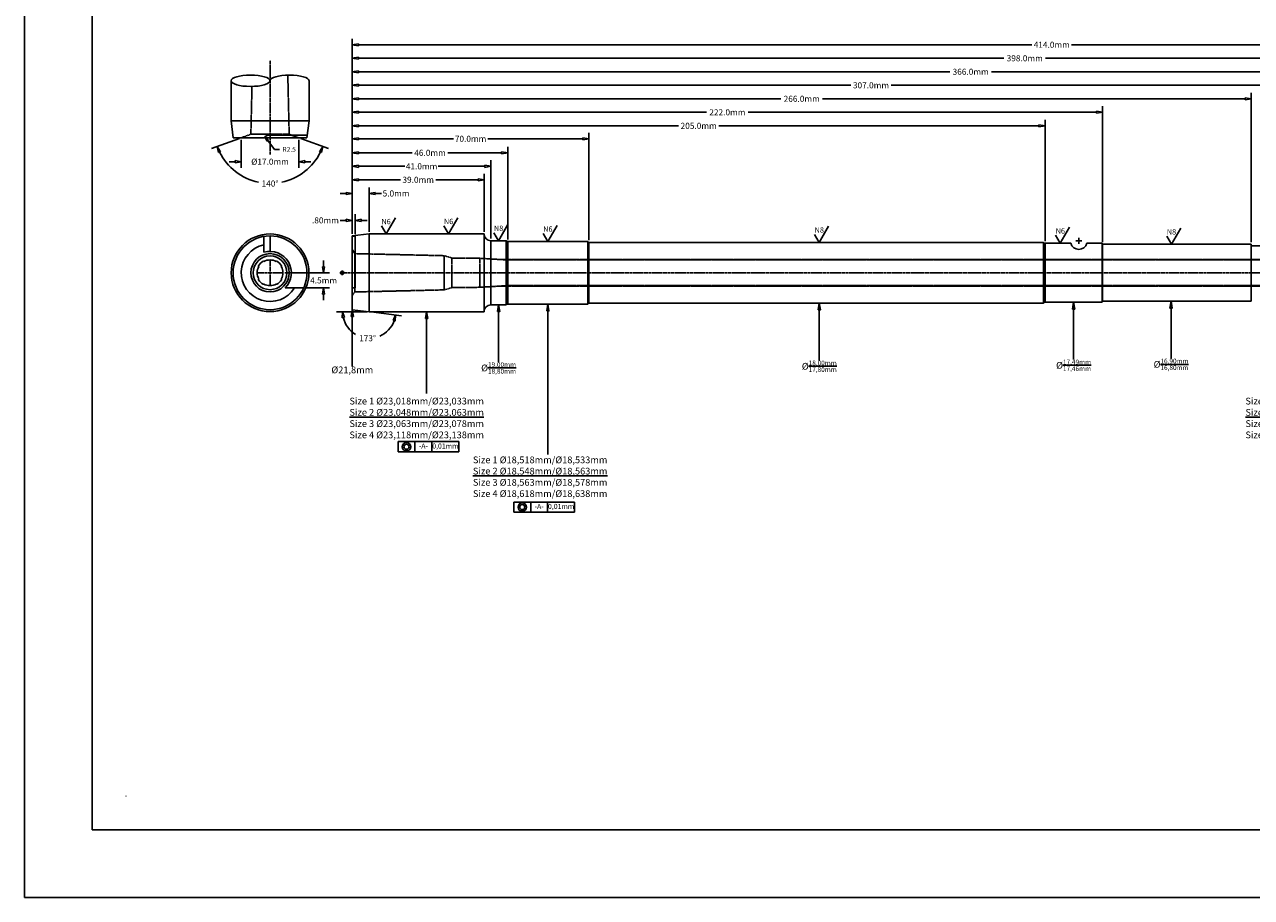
# Model space of a CAD drawing. Units: inches. Extents: x 0 to 594, y 0 to 420.
# Drawn here: x 0 to 363, y 0 to 259 of the extents above; entities that cross this region are included whole.
import ezdxf
from ezdxf.enums import TextEntityAlignment as Align

# ---------------------------------------------------------------- set-up
doc = ezdxf.new("R2010")
doc.units = ezdxf.units.IN
doc.header["$MEASUREMENT"] = 0
for name, pattern in [('CENTER2', [1.125, 0.75, -0.125, 0.125, -0.125]), ('HIDDEN2', [0.1875, 0.125, -0.0625]), ('PHANTOM', [2.5, 1.25, -0.25, 0.25, -0.25, 0.25, -0.25]), ('PHANTOM2', [1.25, 0.625, -0.125, 0.125, -0.125, 0.125, -0.125])]:
    doc.linetypes.add(name, pattern=pattern)
for name, color, linetype in [('BORDER', 7, 'Continuous'), ('BURNOUT', 7, 'Continuous'), ('CENTER', 1, 'CENTER2'), ('CENTERLINE', 1, 'CENTER2'), ('DIMENSION', 3, 'Continuous'), ('HATCH', 253, 'Continuous'), ('HIDDEN', 5, 'HIDDEN2'), ('OBJECT_HEAVY', 9, 'Continuous'), ('OBJECT_LIGHT', 7, 'Continuous'), ('PHANTOM', 252, 'PHANTOM'), ('SECTION', 6, 'PHANTOM2'), ('TEXT', 5, 'Continuous'), ('Title Block', 7, 'Continuous')]:
    doc.layers.add(name, color=color, linetype=linetype)
doc.dimstyles.get("Standard").update_dxf_attribs({"dimscale": 10, "dimtxt": 0.18, "dimasz": 0.18, "dimexe": 0.18, "dimexo": 0.0625, "dimgap": 0.09, "dimtad": 0, "dimtih": 1, "dimtoh": 1, "dimdec": 4, "dimzin": 0, "dimdsep": 46, "dimtxsty": 'Standard', "dimblk": 'CLOSEDBLANK', "dimcen": 0.09, "dimadec": 4, "dimazin": 0, "dimtfac": 1, "dimtdec": 4, "dimtofl": 0, "dimtmove": 0, "dimatfit": 3, "dimldrblk": 'CLOSEDBLANK', "dimfxl": 0, "dimtolj": 1, "dimtzin": 0, "dimarcsym": 0})
doc.dimstyles.new('Standard$0', dxfattribs={"dimscale": 10, "dimtxt": 0.18, "dimasz": 0.18, "dimexe": 0.18, "dimexo": 0.0625, "dimgap": 0.09, "dimtad": 0, "dimtih": 1, "dimtoh": 1, "dimdec": 4, "dimzin": 4, "dimdsep": 46, "dimtxsty": 'Standard', "dimblk": 'CLOSEDBLANK', "dimcen": 0.09, "dimadec": 5, "dimazin": 1, "dimtfac": 1, "dimtdec": 4, "dimtofl": 0, "dimtmove": 0, "dimatfit": 3, "dimldrblk": 'CLOSEDBLANK', "dimfxl": 0, "dimtolj": 1, "dimtzin": 0, "dimarcsym": 0})

# ---------------------------------------------------------------- blocks, each defined once
blk = doc.blocks.new('_ClosedBlank')
at = {"color": 0, "linetype": 'ByBlock', "lineweight": -2}
for p, q in [((-1, 0.17), (0, 0)), ((-1, 0.17), (-1, -0.17)), ((0, 0), (-1, -0.17))]:
    blk.add_line(p, q, dxfattribs=at)
blk = doc.blocks.new('*D21')
at = {"color": 0, "lineweight": -2}
for p, q in [((97, 196.55), (97, 254.33)), ((511, 192.52), (511, 254.33)), ((98.8, 252.53), (298.15, 252.53)), ((509.2, 252.53), (309.85, 252.53))]:
    blk.add_line(p, q, dxfattribs=at)
at = {"layer": 'Defpoints', "color": 0}
for p in [(511, 252.53), (97, 195.92), (511, 191.89)]:
    blk.add_point(p, dxfattribs=at)
at = {"color": 0, "lineweight": -2, "xscale": 1.8, "yscale": 1.8, "zscale": 1.8, "rotation": 180}
blk.add_blockref('_ClosedBlank', (97, 252.53), dxfattribs=at)
at = {"color": 0, "lineweight": -2, "xscale": 1.8, "yscale": 1.8, "zscale": 1.8}
blk.add_blockref('_ClosedBlank', (511, 252.53), dxfattribs=at)
at = {"color": 0, "insert": (304, 252.53), "char_height": 1.8, "attachment_point": 5}
blk.add_mtext('\\A1;414.0mm', dxfattribs=at)
blk = doc.blocks.new('*D7')
at = {"color": 0, "lineweight": -2}
for p, q in [((95.2, 200.53), (93.4, 200.53)), ((97, 196.55), (97, 202.33)), ((97.8, 196.43), (97.8, 202.33)), ((99.6, 200.53), (101.4, 200.53))]:
    blk.add_line(p, q, dxfattribs=at)
at = {"layer": 'Defpoints', "color": 0}
for p in [(97.8, 200.53), (97, 195.92), (97.8, 195.8)]:
    blk.add_point(p, dxfattribs=at)
at = {"color": 0, "lineweight": -2, "xscale": 1.8, "yscale": 1.8, "zscale": 1.8}
blk.add_blockref('_ClosedBlank', (97, 200.53), dxfattribs=at)
at = {"color": 0, "lineweight": -2, "xscale": 1.8, "yscale": 1.8, "zscale": 1.8, "rotation": 180}
blk.add_blockref('_ClosedBlank', (97.8, 200.53), dxfattribs=at)
at = {"color": 0, "insert": (89.05, 200.53), "char_height": 1.8, "attachment_point": 5}
blk.add_mtext('\\A1;.80mm', dxfattribs=at)
blk = doc.blocks.new('*D8')
at = {"color": 0, "lineweight": -2}
for p, q in [((95.2, 208.5), (93.4, 208.5)), ((97, 196.55), (97, 210.3)), ((102, 197.16), (102, 210.3)), ((103.8, 208.5), (105.6, 208.5))]:
    blk.add_line(p, q, dxfattribs=at)
at = {"layer": 'Defpoints', "color": 0}
for p in [(102, 208.5), (102, 196.54), (97, 195.92)]:
    blk.add_point(p, dxfattribs=at)
at = {"color": 0, "lineweight": -2, "xscale": 1.8, "yscale": 1.8, "zscale": 1.8}
blk.add_blockref('_ClosedBlank', (97, 208.5), dxfattribs=at)
at = {"color": 0, "lineweight": -2, "xscale": 1.8, "yscale": 1.8, "zscale": 1.8, "rotation": 180}
blk.add_blockref('_ClosedBlank', (102, 208.5), dxfattribs=at)
at = {"color": 0, "insert": (109.95, 208.5), "char_height": 1.8, "attachment_point": 5}
blk.add_mtext('\\A1;5.0mm', dxfattribs=at)
blk = doc.blocks.new('*D9')
at = {"color": 0, "lineweight": -2}
for p, q in [((97, 196.55), (97, 214.34)), ((136, 197.16), (136, 214.34)), ((98.8, 212.54), (111.25, 212.54)), ((134.2, 212.54), (121.75, 212.54))]:
    blk.add_line(p, q, dxfattribs=at)
at = {"layer": 'Defpoints', "color": 0}
for p in [(136, 212.54), (136, 196.54), (97, 195.92)]:
    blk.add_point(p, dxfattribs=at)
at = {"color": 0, "lineweight": -2, "xscale": 1.8, "yscale": 1.8, "zscale": 1.8, "rotation": 180}
blk.add_blockref('_ClosedBlank', (97, 212.54), dxfattribs=at)
at = {"color": 0, "lineweight": -2, "xscale": 1.8, "yscale": 1.8, "zscale": 1.8}
blk.add_blockref('_ClosedBlank', (136, 212.54), dxfattribs=at)
at = {"color": 0, "insert": (116.5, 212.54), "char_height": 1.8, "attachment_point": 5}
blk.add_mtext('\\A1;39.0mm', dxfattribs=at)
blk = doc.blocks.new('*D10')
at = {"color": 0, "lineweight": -2}
for p, q in [((97, 196.55), (97, 218.33)), ((138, 195.13), (138, 218.33)), ((98.8, 216.53), (112.55, 216.53)), ((136.2, 216.53), (122.45, 216.53))]:
    blk.add_line(p, q, dxfattribs=at)
at = {"layer": 'Defpoints', "color": 0}
for p in [(97, 216.53), (97, 195.92), (138, 194.5)]:
    blk.add_point(p, dxfattribs=at)
at = {"color": 0, "lineweight": -2, "xscale": 1.8, "yscale": 1.8, "zscale": 1.8, "rotation": 180}
blk.add_blockref('_ClosedBlank', (97, 216.53), dxfattribs=at)
at = {"color": 0, "lineweight": -2, "xscale": 1.8, "yscale": 1.8, "zscale": 1.8}
blk.add_blockref('_ClosedBlank', (138, 216.53), dxfattribs=at)
at = {"color": 0, "insert": (117.5, 216.53), "char_height": 1.8, "attachment_point": 5}
blk.add_mtext('\\A1;41.0mm', dxfattribs=at)
blk = doc.blocks.new('*D11')
at = {"color": 0, "lineweight": -2}
for p, q in [((97, 196.55), (97, 222.33)), ((143, 194.9), (143, 222.33)), ((98.8, 220.53), (114.75, 220.53)), ((141.2, 220.53), (125.25, 220.53))]:
    blk.add_line(p, q, dxfattribs=at)
at = {"layer": 'Defpoints', "color": 0}
for p in [(97, 220.53), (97, 195.92), (143, 194.28)]:
    blk.add_point(p, dxfattribs=at)
at = {"color": 0, "lineweight": -2, "xscale": 1.8, "yscale": 1.8, "zscale": 1.8, "rotation": 180}
blk.add_blockref('_ClosedBlank', (97, 220.53), dxfattribs=at)
at = {"color": 0, "lineweight": -2, "xscale": 1.8, "yscale": 1.8, "zscale": 1.8}
blk.add_blockref('_ClosedBlank', (143, 220.53), dxfattribs=at)
at = {"color": 0, "insert": (120, 220.53), "char_height": 1.8, "attachment_point": 5}
blk.add_mtext('\\A1;46.0mm', dxfattribs=at)
blk = doc.blocks.new('*D12')
at = {"color": 0, "lineweight": -2}
for p, q in [((97, 196.55), (97, 226.48)), ((167, 194.63), (167, 226.48)), ((98.8, 224.68), (126.9, 224.68)), ((165.2, 224.68), (137.1, 224.68))]:
    blk.add_line(p, q, dxfattribs=at)
at = {"layer": 'Defpoints', "color": 0}
for p in [(97, 224.68), (97, 195.92), (167, 194)]:
    blk.add_point(p, dxfattribs=at)
at = {"color": 0, "lineweight": -2, "xscale": 1.8, "yscale": 1.8, "zscale": 1.8, "rotation": 180}
blk.add_blockref('_ClosedBlank', (97, 224.68), dxfattribs=at)
at = {"color": 0, "lineweight": -2, "xscale": 1.8, "yscale": 1.8, "zscale": 1.8}
blk.add_blockref('_ClosedBlank', (167, 224.68), dxfattribs=at)
at = {"color": 0, "insert": (132, 224.68), "char_height": 1.8, "attachment_point": 5}
blk.add_mtext('\\A1;70.0mm', dxfattribs=at)
blk = doc.blocks.new('*D13')
at = {"color": 0, "lineweight": -2}
for p, q in [((97, 196.55), (97, 230.33)), ((302, 194.35), (302, 230.33)), ((98.8, 228.53), (193.5, 228.53)), ((300.2, 228.53), (205.5, 228.53))]:
    blk.add_line(p, q, dxfattribs=at)
at = {"layer": 'Defpoints', "color": 0}
for p in [(97, 228.53), (97, 195.92), (302, 193.73)]:
    blk.add_point(p, dxfattribs=at)
at = {"color": 0, "lineweight": -2, "xscale": 1.8, "yscale": 1.8, "zscale": 1.8, "rotation": 180}
blk.add_blockref('_ClosedBlank', (97, 228.53), dxfattribs=at)
at = {"color": 0, "lineweight": -2, "xscale": 1.8, "yscale": 1.8, "zscale": 1.8}
blk.add_blockref('_ClosedBlank', (302, 228.53), dxfattribs=at)
at = {"color": 0, "insert": (199.5, 228.53), "char_height": 1.8, "attachment_point": 5}
blk.add_mtext('\\A1;205.0mm', dxfattribs=at)
blk = doc.blocks.new('*D14')
at = {"color": 0, "lineweight": -2}
for p, q in [((97, 196.55), (97, 234.33)), ((98.8, 232.53), (201.85, 232.53)), ((317.2, 232.53), (214.15, 232.53)), ((319, 194.08), (319, 234.33))]:
    blk.add_line(p, q, dxfattribs=at)
at = {"layer": 'Defpoints', "color": 0}
for p in [(97, 232.53), (97, 195.92), (319, 193.45)]:
    blk.add_point(p, dxfattribs=at)
at = {"color": 0, "lineweight": -2, "xscale": 1.8, "yscale": 1.8, "zscale": 1.8, "rotation": 180}
blk.add_blockref('_ClosedBlank', (97, 232.53), dxfattribs=at)
at = {"color": 0, "lineweight": -2, "xscale": 1.8, "yscale": 1.8, "zscale": 1.8}
blk.add_blockref('_ClosedBlank', (319, 232.53), dxfattribs=at)
at = {"color": 0, "insert": (208, 232.53), "char_height": 1.8, "attachment_point": 5}
blk.add_mtext('\\A1;222.0mm', dxfattribs=at)
blk = doc.blocks.new('*D15')
at = {"color": 0, "lineweight": -2}
for p, q in [((97, 196.55), (97, 238.33)), ((98.8, 236.53), (223.85, 236.53)), ((361.2, 236.53), (236.15, 236.53)), ((363, 194.08), (363, 238.33))]:
    blk.add_line(p, q, dxfattribs=at)
at = {"layer": 'Defpoints', "color": 0}
for p in [(97, 236.53), (97, 195.92), (363, 193.45)]:
    blk.add_point(p, dxfattribs=at)
at = {"color": 0, "lineweight": -2, "xscale": 1.8, "yscale": 1.8, "zscale": 1.8, "rotation": 180}
blk.add_blockref('_ClosedBlank', (97, 236.53), dxfattribs=at)
at = {"color": 0, "lineweight": -2, "xscale": 1.8, "yscale": 1.8, "zscale": 1.8}
blk.add_blockref('_ClosedBlank', (363, 236.53), dxfattribs=at)
at = {"color": 0, "insert": (230, 236.53), "char_height": 1.8, "attachment_point": 5}
blk.add_mtext('\\A1;266.0mm', dxfattribs=at)
blk = doc.blocks.new('*D16')
at = {"color": 0, "lineweight": -2}
for p, q in [((97, 196.55), (97, 242.33)), ((98.8, 240.53), (244.5, 240.53)), ((402.2, 240.53), (256.5, 240.53)), ((404, 193.38), (404, 242.33))]:
    blk.add_line(p, q, dxfattribs=at)
at = {"layer": 'Defpoints', "color": 0}
for p in [(97, 240.53), (97, 195.92), (404, 192.75)]:
    blk.add_point(p, dxfattribs=at)
at = {"color": 0, "lineweight": -2, "xscale": 1.8, "yscale": 1.8, "zscale": 1.8, "rotation": 180}
blk.add_blockref('_ClosedBlank', (97, 240.53), dxfattribs=at)
at = {"color": 0, "lineweight": -2, "xscale": 1.8, "yscale": 1.8, "zscale": 1.8}
blk.add_blockref('_ClosedBlank', (404, 240.53), dxfattribs=at)
at = {"color": 0, "insert": (250.5, 240.53), "char_height": 1.8, "attachment_point": 5}
blk.add_mtext('\\A1;307.0mm', dxfattribs=at)
blk = doc.blocks.new('*D17')
at = {"color": 0, "lineweight": -2}
for p, q in [((97, 196.55), (97, 246.33)), ((98.8, 244.53), (273.85, 244.53)), ((461.2, 244.53), (286.15, 244.53)), ((463, 193.15), (463, 246.33))]:
    blk.add_line(p, q, dxfattribs=at)
at = {"layer": 'Defpoints', "color": 0}
for p in [(97, 244.53), (97, 195.92), (463, 192.53)]:
    blk.add_point(p, dxfattribs=at)
at = {"color": 0, "lineweight": -2, "xscale": 1.8, "yscale": 1.8, "zscale": 1.8, "rotation": 180}
blk.add_blockref('_ClosedBlank', (97, 244.53), dxfattribs=at)
at = {"color": 0, "lineweight": -2, "xscale": 1.8, "yscale": 1.8, "zscale": 1.8}
blk.add_blockref('_ClosedBlank', (463, 244.53), dxfattribs=at)
at = {"color": 0, "insert": (280, 244.53), "char_height": 1.8, "attachment_point": 5}
blk.add_mtext('\\A1;366.0mm', dxfattribs=at)
blk = doc.blocks.new('*D18')
at = {"color": 0, "lineweight": -2}
for p, q in [((97, 196.55), (97, 250.33)), ((98.8, 248.53), (289.85, 248.53)), ((493.2, 248.53), (302.15, 248.53)), ((495, 192.15), (495, 250.33))]:
    blk.add_line(p, q, dxfattribs=at)
at = {"layer": 'Defpoints', "color": 0}
for p in [(495, 248.53), (97, 195.92), (495, 191.53)]:
    blk.add_point(p, dxfattribs=at)
at = {"color": 0, "lineweight": -2, "xscale": 1.8, "yscale": 1.8, "zscale": 1.8, "rotation": 180}
blk.add_blockref('_ClosedBlank', (97, 248.53), dxfattribs=at)
at = {"color": 0, "lineweight": -2, "xscale": 1.8, "yscale": 1.8, "zscale": 1.8}
blk.add_blockref('_ClosedBlank', (495, 248.53), dxfattribs=at)
at = {"color": 0, "insert": (296, 248.53), "char_height": 1.8, "attachment_point": 5}
blk.add_mtext('\\A1;398.0mm', dxfattribs=at)
blk = doc.blocks.new('*D23')
at = {"color": 0, "lineweight": -2}
for p, q in [((101.37, 173.47), (92.34, 173.47)), ((102.62, 173.39), (111.59, 172.29))]:
    blk.add_line(p, q, dxfattribs=at)
for start, end in [(193.1453, 238.7414), (293.3785, 339.8547)]:
    blk.add_arc((102, 173.47), 7.86, start, end, dxfattribs=at)
at = {"layer": 'Defpoints', "color": 0}
for p in [(97, 174.08), (102, 173.47), (102, 173.47), (136, 173.47), (97.79, 166.82)]:
    blk.add_point(p, dxfattribs=at)
at = {"color": 0, "lineweight": -2, "xscale": 1.8, "yscale": 1.8, "zscale": 1.8}
for p, rotation in [((94.14, 173.47), 96.57265869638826), ((109.8, 172.51), 76.42734130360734)]:
    blk.add_blockref('_ClosedBlank', p, dxfattribs=dict(at, rotation=rotation))
at = {"color": 0, "insert": (101.52, 165.62), "char_height": 1.8, "attachment_point": 5}
blk.add_mtext('\\A1;173°', dxfattribs=at)
blk = doc.blocks.new('*D24')
at = {"color": 0, "lineweight": -2}
for p, q in [((88.5, 186.8), (88.5, 188.6)), ((77.08, 185), (90.3, 185)), ((83.23, 180.5), (90.3, 180.5)), ((88.5, 178.7), (88.5, 176.9))]:
    blk.add_line(p, q, dxfattribs=at)
at = {"layer": 'Defpoints', "color": 0}
for p in [(76.46, 185), (88.5, 185), (82.6, 180.5)]:
    blk.add_point(p, dxfattribs=at)
at = {"color": 0, "lineweight": -2, "xscale": 1.8, "yscale": 1.8, "zscale": 1.8}
for p, rotation in [((88.5, 185), 270), ((88.5, 180.5), 90)]:
    blk.add_blockref('_ClosedBlank', p, dxfattribs=dict(at, rotation=rotation))
at = {"color": 0, "insert": (88.5, 182.75), "char_height": 1.8, "attachment_point": 5}
blk.add_mtext('\\A1;4.5mm', dxfattribs=at)
blk = doc.blocks.new('*D25')
at = {"color": 0, "lineweight": -2}
for p, q in [((73.99, 221.56), (72, 224.14)), ((75.43, 221.56), (73.99, 221.56))]:
    blk.add_line(p, q, dxfattribs=at)
at = {"layer": 'Defpoints', "color": 0}
for p in [(71.12, 225.28), (72.65, 223.3)]:
    blk.add_point(p, dxfattribs=at)
at = {"color": 0, "lineweight": -2, "xscale": 1.44, "yscale": 1.44, "zscale": 1.44, "rotation": 127.7379653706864}
blk.add_blockref('_ClosedBlank', (71.12, 225.28), dxfattribs=at)
at = {"color": 0, "insert": (78.31, 221.56), "char_height": 1.44, "attachment_point": 5}
blk.add_mtext('\\A1;R2.5', dxfattribs=at)
blk = doc.blocks.new('*D32')
at = {"color": 0, "lineweight": -2}
for p, q in [((63.57, 224.79), (55.32, 221.78)), ((81.74, 224.79), (89.99, 221.78))]:
    blk.add_line(p, q, dxfattribs=at)
for start, end in [(206.197, 258.0416), (281.9584, 333.803)]:
    blk.add_arc((72.65, 228.1), 16.65, start, end, dxfattribs=at)
at = {"layer": 'Defpoints', "color": 0}
for p in [(66.98, 226.03), (78.32, 226.03), (64.15, 225), (81.15, 225), (66.06, 212.81)]:
    blk.add_point(p, dxfattribs=at)
at = {"color": 0, "lineweight": -2, "xscale": 1.8, "yscale": 1.8, "zscale": 1.8}
for p, rotation in [((57.01, 222.4), 113.0985010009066), ((88.3, 222.4), 66.90149899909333)]:
    blk.add_blockref('_ClosedBlank', p, dxfattribs=dict(at, rotation=rotation))
at = {"color": 0, "insert": (72.65, 211.44), "char_height": 1.8, "attachment_point": 5}
blk.add_mtext('\\A1;140°', dxfattribs=at)
blk = doc.blocks.new('*D33')
at = {"color": 0, "lineweight": -2}
for p, q in [((64.15, 224.38), (64.15, 216.1)), ((81.15, 224.38), (81.15, 216.1)), ((62.35, 217.9), (60.55, 217.9)), ((82.95, 217.9), (84.75, 217.9))]:
    blk.add_line(p, q, dxfattribs=at)
at = {"layer": 'Defpoints', "color": 0}
for p in [(64.15, 225), (81.15, 225), (81.15, 217.9)]:
    blk.add_point(p, dxfattribs=at)
at = {"color": 0, "lineweight": -2, "xscale": 1.8, "yscale": 1.8, "zscale": 1.8}
blk.add_blockref('_ClosedBlank', (64.15, 217.9), dxfattribs=at)
at = {"color": 0, "lineweight": -2, "xscale": 1.8, "yscale": 1.8, "zscale": 1.8, "rotation": 180}
blk.add_blockref('_ClosedBlank', (81.15, 217.9), dxfattribs=at)
at = {"color": 0, "insert": (72.65, 217.9), "char_height": 1.8, "attachment_point": 5}
blk.add_mtext('\\A1;%%C17.0mm', dxfattribs=at)

msp = doc.modelspace()

# ---------------------------------------------------------------- hatches: boundary and pattern name
at = {"layer": 'CENTER'}
h = msp.add_hatch(dxfattribs=at)
h.set_pattern_fill('ANSI31', color=256, style=0)
h.set_pattern_definition([(45, (45, 135), (-0.08838835, 0.08838835), [])])
h.paths.add_polyline_path([(93.99996, 185.50003, 0.414213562), (93.49996, 185.00003), (93.99996, 185.00003)])
h.paths.add_polyline_path([(94.49996, 185.00003), (93.99996, 185.00003), (93.99996, 184.50003, 0.414213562)])

# ---------------------------------------------------------------- linework, layer by layer
for p, q in [((61.11496, 230.00003), (61.11496, 241.86689)), ((84.18496, 230.00003), (84.18496, 241.86689)), ((84.18496, 230.00003), (61.11496, 230.00003)), ((61.72888, 225.00003), (61.11496, 230.00003)), ((83.57104, 225.00003), (84.18496, 230.00003)), ((83.66927, 225.80003), (72.64996, 225.80003)), ((78.95198, 225.80003), (81.14996, 225.00003)), ((83.57104, 225.00003), (61.72888, 225.00003)), ((106.99996, 196.50003), (109.74959, 201.26253)), ((125.49996, 196.53503), (128.24959, 201.29753)), ((96.99996, 195.92111), (101.99996, 196.53503)), ((101.99996, 196.53503), (135.99996, 196.53503)), ((101.99996, 173.46503), (101.99996, 196.53503)), ((105.62514, 198.88128), (106.99996, 196.50003)), ((124.12514, 198.91628), (125.49996, 196.53503)), ((135.99996, 173.46503), (135.99996, 196.53503)), ((138.91635, 196.88128), (140.29117, 194.50003)), ((140.29117, 194.50003), (143.0408, 199.26253)), ((153.50014, 196.65628), (154.87496, 194.27503)), ((154.87496, 194.27503), (157.62459, 199.03753)), ((233.82106, 196.38128), (235.19588, 194.00003)), ((235.19588, 194.00003), (237.94551, 198.76253)), ((305.15281, 196.10628), (306.52763, 193.72503)), ((306.52763, 193.72503), (309.27726, 198.48753)), ((339.42545, 193.45003), (342.17508, 198.21253)), ((70.81693, 191.05965), (70.81693, 195.7662)), ((72.64996, 191.33083), (72.64996, 195.92113)), ((96.99996, 174.07895), (96.99996, 195.92111)), ((96.99996, 195.80329), (97.79996, 195.80329)), ((97.79996, 180.50003), (97.79996, 195.80329)), ((137.99996, 194.50003), (142.58238, 194.50003)), ((137.99996, 175.50003), (137.99996, 194.50003)), ((142.58238, 194.50003), (142.58238, 175.50003)), ((142.99996, 194.27503), (166.74996, 194.27503)), ((142.99996, 175.72503), (142.99996, 194.27503)), ((166.74996, 194.27503), (166.74996, 175.72503)), ((166.99996, 194.00003), (301.55601, 194.00003)), ((166.99996, 176.00003), (166.99996, 194.00003)), ((301.55601, 194.00003), (301.55601, 176.00003)), ((301.99996, 193.72503), (309.60649, 193.72503)), ((301.99996, 193.72503), (301.99996, 176.27503)), ((314.39343, 193.72503), (318.89996, 193.72503)), ((318.89996, 193.72503), (318.89996, 176.27503)), ((318.99996, 193.45003), (362.99996, 193.45003)), ((318.99996, 193.45003), (318.99996, 176.55003)), ((338.05063, 195.83128), (339.42545, 193.45003)), ((362.99996, 193.45003), (362.99996, 176.55003)), ((363.09996, 193.02503), (403.89996, 193.02503)), ((97.69996, 190.67505), (96.99996, 191.88748)), ((97.69996, 185.70003), (97.69996, 190.67505)), ((97.69996, 180.50003), (97.69996, 185.70003)), ((77.10294, 180.50003), (82.60087, 180.50003)), ((96.99996, 180.50003), (97.79996, 180.50003)), ((137.99996, 175.50003), (142.58238, 175.50003)), ((142.99996, 175.72503), (166.74996, 175.72503)), ((166.99996, 176.00003), (301.55601, 176.00003)), ((301.99996, 176.27503), (318.89996, 176.27503)), ((318.99996, 176.55003), (362.99996, 176.55003)), ((96.99996, 174.07895), (101.99996, 173.46503)), ((101.99996, 173.46503), (135.99996, 173.46503))]:
    msp.add_line(p, q)
at = {"ltscale": 0.75}
msp.add_line((30, 30), (30.03125, 30), dxfattribs=at)
for points in [[(0, 0), (594, 0), (594, 420), (0, 420)], [(20, 20), (574, 20), (574, 400), (20, 400)]]:
    msp.add_lwpolyline(points, close=True)
for radius in [11.5, 10.9211, 5.67115, 5]:
    msp.add_circle((72.64996, 185.00003), radius)
for centre, radius, start, end in [((72.64996, 223.30003), 2.5, 90, 137.156357), ((137.99996, 196.50003), 2, 180, 270), ((72.64996, 185.00003), 8.5, 102.4537006, 328.0342812), ((142.99996, 194.77503), 0.5, 213.367013, 270), ((166.99996, 194.25003), 0.25, 180, 270), ((302.00252, 194.22502), 0.5, 206.7428404, 270), ((311.99996, 194.44703), 2.5, 196.7861274, 343.2138726), ((318.99996, 193.55003), 0.1, 180, 270), ((363.09996, 193.12503), 0.1, 180, 270), ((72.64996, 185.00003), 6.3308, 314.6990904, 106.8305173), ((137.99996, 173.50003), 2, 90, 180), ((142.99996, 175.22503), 0.5, 90, 146.632987), ((166.99996, 175.75003), 0.25, 90, 180), ((301.99996, 175.77503), 0.5, 90, 153.256316), ((318.99996, 176.45003), 0.1, 90, 180), ((363.09996, 176.87503), 0.1, 90, 180)]:
    msp.add_arc(centre, radius, start, end)
at = {"ltscale": 0.25}
for centre, radius, start, end in [((72.64996, 185.00003), 3.81, 151.3407406, 208.6592594), ((69.3825, 186.95957), 0.1524, 149.0482979, 240.1945192), ((72.64996, 185.00003), 3.9624, 120.9517021, 149.0482979), ((70.69042, 188.26749), 0.1524, 29.8054808, 120.9517021), ((72.64996, 185.00003), 3.81, 61.3407406, 118.6592594), ((74.6095, 188.26749), 0.1524, 59.0482979, 150.1945192), ((72.64996, 185.00003), 3.9624, 30.9517021, 59.0482979), ((75.91742, 186.95957), 0.1524, 299.8054808, 30.9517021), ((72.64996, 185.00003), 3.81, 331.3407406, 28.6592594), ((69.3825, 183.04049), 0.1524, 119.8054808, 210.9517021), ((72.64996, 185.00003), 3.9624, 210.9517021, 239.0482979), ((70.69042, 181.73257), 0.1524, 239.0482979, 330.1945192), ((72.64996, 185.00003), 3.81, 241.3407406, 298.6592594), ((74.6095, 181.73257), 0.1524, 209.8054808, 300.9517021), ((72.64996, 185.00003), 3.9624, 300.9517021, 329.0482979), ((75.91742, 183.04049), 0.1524, 329.0482979, 60.1945192)]:
    msp.add_arc(centre, radius, start, end, dxfattribs=at)
msp.add_ellipse((66.88246, 241.86689), major_axis=(-5.7675, 0), ratio=0.291449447)
msp.add_ellipse((78.41746, 241.86689), major_axis=(-5.7675, 0), ratio=0.291449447, start_param=3.141592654, end_param=6.283185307)
at = {"layer": 'BORDER', "ltscale": 0.75}
msp.add_line((30, 30), (30.02706, 30.01562), dxfattribs=at)
at = {"layer": 'BURNOUT', "ltscale": 0.75}
msp.add_line((30, 30), (30.0221, 30.0221), dxfattribs=at)
at = {"layer": 'CENTER'}
for p, q in [((311.09996, 194.44703), (312.89996, 194.44703)), ((311.99996, 193.54703), (311.99996, 195.34703)), ((93.99996, 184.50003), (93.99996, 185.50003))]:
    msp.add_line(p, q, dxfattribs=at)
msp.add_circle((93.99996, 185.00003), 0.5, dxfattribs=at)
at = {"layer": 'CENTERLINE'}
for p, q in [((72.64996, 220.00003), (72.64996, 247.89728)), ((72.64996, 181.19003), (72.64996, 188.81003)), ((68.83996, 185.00003), (76.45996, 185.00003)), ((93.49996, 185.00003), (513.99996, 185.00003))]:
    msp.add_line(p, q, dxfattribs=at)
at = {"layer": 'CENTERLINE', "ltscale": 0.75}
msp.add_line((30, 30), (30.01562, 30.02706), dxfattribs=at)
at = {"layer": 'Defpoints', "ltscale": 0.75}
msp.add_line((30, 30), (30, 30.03125), dxfattribs=at)
at = {"layer": 'DIMENSION', "ltscale": 0.75}
msp.add_line((30, 30), (29.99191, 30.03018), dxfattribs=at)
at = {"layer": 'HATCH', "ltscale": 0.75}
msp.add_line((30, 30), (29.96982, 30.00809), dxfattribs=at)
at = {"layer": 'HIDDEN'}
for p, q in [((78.04196, 238.03003), (77.91283, 243.54138)), ((67.25796, 238.03003), (67.30858, 240.19055)), ((66.98254, 226.031), (67.25796, 238.03003)), ((78.31738, 226.031), (78.04196, 238.03003)), ((66.98254, 226.031), (64.14996, 225.00003)), ((78.31738, 226.031), (66.98254, 226.031)), ((78.31738, 226.031), (78.95198, 225.80003)), ((97.69996, 190.67505), (110.02996, 190.39203)), ((110.02996, 190.39203), (124.19996, 190.06003)), ((124.19996, 179.94003), (124.19996, 190.06003)), ((124.19996, 190.06003), (125.34996, 189.71503)), ((125.34996, 189.71503), (126.49996, 189.37003)), ((126.49996, 180.63003), (126.49996, 189.37003)), ((126.49996, 189.37003), (134.69996, 189.30003)), ((134.69996, 180.70003), (134.69996, 189.30003)), ((134.69996, 189.30003), (142.69996, 188.81003)), ((140.2118, 188.96243), (510.99996, 188.96243)), ((142.69996, 188.81003), (510.99996, 188.81003)), ((142.69996, 181.19003), (142.69996, 188.81003)), ((97.69996, 179.32501), (96.99996, 178.11258)), ((97.69996, 179.32501), (97.69996, 180.50003)), ((97.69996, 179.32501), (110.02996, 179.60803)), ((110.02996, 179.60803), (124.19996, 179.94003)), ((124.19996, 179.94003), (125.34996, 180.28503)), ((125.34996, 180.28503), (126.49996, 180.63003)), ((126.49996, 180.63003), (134.69996, 180.70003)), ((134.69996, 180.70003), (142.69996, 181.19003)), ((140.2118, 181.03763), (510.99996, 181.03763)), ((142.69996, 181.19003), (510.99996, 181.19003))]:
    msp.add_line(p, q, dxfattribs=at)
at = {"layer": 'HIDDEN', "ltscale": 0.75}
msp.add_line((30, 30), (29.96875, 30), dxfattribs=at)
at = {"layer": 'OBJECT_HEAVY', "ltscale": 0.75}
msp.add_line((30, 30), (29.97294, 29.98438), dxfattribs=at)
at = {"layer": 'OBJECT_LIGHT', "ltscale": 0.75}
msp.add_line((30, 30), (29.9779, 29.9779), dxfattribs=at)
at = {"layer": 'PHANTOM', "ltscale": 0.75}
msp.add_line((30, 30), (30, 29.96875), dxfattribs=at)
at = {"layer": 'SECTION', "ltscale": 0.75}
msp.add_line((30, 30), (30.00809, 29.96982), dxfattribs=at)
at = {"layer": 'TEXT', "color": 7}
for p, q in [((110.5396, 132), (110.5396, 135)), ((110.5396, 135), (115.5396, 135)), ((115.5396, 135), (120.5396, 135)), ((115.5396, 132), (115.5396, 135)), ((120.5396, 135), (128.5396, 135)), ((120.5396, 132), (120.5396, 135)), ((128.5396, 132), (128.5396, 135)), ((110.5396, 132), (115.5396, 132)), ((115.5396, 132), (120.5396, 132)), ((120.5396, 132), (128.5396, 132)), ((144.79924, 114.1172), (144.79924, 117.1172)), ((144.79924, 117.1172), (149.79924, 117.1172)), ((149.79924, 117.1172), (154.79924, 117.1172)), ((149.79924, 114.1172), (149.79924, 117.1172)), ((154.79924, 117.1172), (162.79924, 117.1172)), ((154.79924, 114.1172), (154.79924, 117.1172)), ((162.79924, 114.1172), (162.79924, 117.1172)), ((144.79924, 114.1172), (149.79924, 114.1172)), ((149.79924, 114.1172), (154.79924, 114.1172)), ((154.79924, 114.1172), (162.79924, 114.1172))]:
    msp.add_line(p, q, dxfattribs=at)
at = {"layer": 'TEXT', "ltscale": 0.75}
msp.add_line((30, 30), (30.0221, 29.9779), dxfattribs=at)
at = {"layer": 'TEXT', "color": 7}
for centre, radius in [((113.0396, 133.5), 1.25), ((113.0396, 133.5), 0.75), ((147.29924, 115.6172), 1.25), ((147.29924, 115.6172), 0.75)]:
    msp.add_circle(centre, radius, dxfattribs=at)
at = {"layer": 'Title Block', "ltscale": 0.75}
msp.add_line((30, 30), (30.02706, 29.98438), dxfattribs=at)

# ---------------------------------------------------------------- texts
for s, p in [('N6', (106.99996, 198.88128)), ('N6', (125.49996, 198.91628)), ('N8', (140.29117, 196.88128)), ('N6', (154.87496, 196.65628)), ('N8', (235.19588, 196.38128)), ('N6', (306.52763, 196.10628)), ('N8', (339.42545, 195.83128))]:
    msp.add_text(s, height=1.5875).set_placement(p, align=Align.BOTTOM_CENTER)
at = {"char_height": 2, "width": 10.5482646, "attachment_point": 2}
for s, insert in [('\\A1;%%C21,8mm', (96.99996, 157.24774)), ('\\A1;%%C{\\H0.7x;\\S19,00mm/18,80mm;}', (140.29117, 158.50003)), ('\\A1;%%C{\\H0.7x;\\S18,00mm/17,80mm;}', (235.1946, 159.00003)), ('\\A1;%%C{\\H0.7x;\\S17,49mm/17,46mm;}', (310.44996, 159.27503)), ('\\A1;%%C{\\H0.7x;\\S16,90mm/16,80mm;}', (339.30998, 159.57003))]:
    msp.add_mtext(s, dxfattribs=dict(at, insert=insert))
at = {"layer": 'TEXT', "color": 7}
for s, insert, char_height, width, attachment_point in [('\\A1;Size 1 %%C23,018mm/%%C23,033mm\\P{\\LSize 2 %%C23,048mm/%%C23,063mm}\\PSize 3 %%C23,063mm/%%C23,078mm\\PSize 4 %%C23,118mm/%%C23,138mm', (96.15454, 148), 2, 48.5376086, 1), ('\\A1;Size 1 %%C16,018mm/%%C16,033mm\\P{\\LSize 2 %%C16,048mm/%%C16,063mm}\\PSize 3 %%C16,063mm/%%C16,078mm\\PSize 4 %%C16,118mm/%%C16,138mm', (361.31639, 148), 2, 48.5376086, 1), ('-A-', (118.0396, 133.5), 1.5, 1.19634, 5), ('0,01mm', (124.5396, 133.5), 1.5, 6.6720954, 5), ('\\A1;Size 1 %%C18,518mm/%%C18,533mm\\P{\\LSize 2 %%C18,548mm/%%C18,563mm}\\PSize 3 %%C18,563mm/%%C18,578mm\\PSize 4 %%C18,618mm/%%C18,638mm', (132.69139, 130.60018), 2, 48.5376086, 1), ('-A-', (152.29924, 115.6172), 1.5, 1.19634, 5), ('0,01mm', (158.79924, 115.6172), 1.5, 6.6720954, 5)]:
    msp.add_mtext(s, dxfattribs=dict(at, insert=insert, char_height=char_height, width=width, attachment_point=attachment_point))

# ---------------------------------------------------------------- dimensions: what is measured, and where the dimension line sits
for base, p1, p2, picture, middle in [((510.99996, 252.52503), (96.99996, 195.92111), (510.99996, 191.89178), '*D21', (303.99996, 252.52503)), ((494.99996, 248.52503), (96.99996, 195.92111), (494.99996, 191.52503), '*D18', (295.99996, 248.52503)), ((96.99996, 244.52503), (462.99996, 192.52503), (96.99996, 195.92111), '*D17', (279.99996, 244.52503)), ((96.99996, 240.52503), (403.99996, 192.75003), (96.99996, 195.92111), '*D16', (250.49996, 240.52503)), ((96.99996, 236.52503), (362.99996, 193.45003), (96.99996, 195.92111), '*D15', (229.99996, 236.52503)), ((96.99996, 232.52503), (318.99996, 193.45003), (96.99996, 195.92111), '*D14', (207.99996, 232.52503)), ((96.99996, 228.52503), (302.00315, 193.72502), (96.99996, 195.92111), '*D13', (199.50155, 228.52503)), ((96.99996, 224.67503), (166.99996, 194.00003), (96.99996, 195.92111), '*D12', (131.99996, 224.67503)), ((96.99996, 220.52503), (142.99996, 194.27565), (96.99996, 195.92111), '*D11', (119.99996, 220.52503)), ((96.99996, 216.52503), (137.99996, 194.50003), (96.99996, 195.92111), '*D10', (117.49996, 216.52503)), ((135.99996, 212.53503), (96.99996, 195.92111), (135.99996, 196.53503), '*D9', (116.49996, 212.53503)), ((101.99996, 208.50003), (96.99996, 195.92111), (101.99996, 196.53503), '*D8', (109.94996, 208.50003))]:
    dim = msp.add_linear_dim(base=base, p1=p1, p2=p2, dimstyle='Standard$0', override={"dimscale": 10, "dimdec": 1, "dimpost": 'mm', "dimblk1": 'ClosedBlank', "dimblk2": 'ClosedBlank', "dimsah": 1})
    dim.commit()
    dim.dimension.update_dxf_attribs({"geometry": picture, "text_midpoint": middle})
for base, line1, line2, picture, middle in [((66.05882, 212.80646), ((78.32488, 226.031), (81.15371, 225.00139)), ((66.98254, 226.031), (64.15371, 225.00139)), '*D32', (72.65371, 211.44472)), ((97.79459, 166.82135), ((101.99996, 173.46503), (135.99996, 173.46503)), ((96.99996, 174.07895), (101.99996, 173.46503)), '*D23', (101.51995, 165.6169))]:
    dim = msp.add_angular_dim_2l(base=base, line1=line1, line2=line2, dimstyle='Standard', override={"dimadec": 0})
    dim.commit()
    dim.dimension.update_dxf_attribs({"geometry": picture, "text_midpoint": middle})
dim = msp.add_radius_dim(center=(72.64996, 223.30003), mpoint=(71.11983, 225.27707), dimstyle='Standard', override={"dimscale": 8, "dimdec": 1, "dimtmove": 1})
dim.commit()
dim.dimension.update_dxf_attribs({"geometry": '*D25', "text_midpoint": (73.99376, 221.56374), "dimtype": 164})
dim = msp.add_linear_dim(base=(81.15371, 217.90411), p1=(64.15371, 225.00139), p2=(81.15371, 225.00139), text='%%C<>', dimstyle='Standard$0', override={"dimdec": 1, "dimpost": 'mm'})
dim.commit()
dim.dimension.update_dxf_attribs({"geometry": '*D33', "text_midpoint": (72.65371, 217.90411)})
dim = msp.add_linear_dim(base=(97.79996, 200.52503), p1=(96.99996, 195.92111), p2=(97.79996, 195.80329), dimstyle='Standard$0', override={"dimscale": 10, "dimdec": 2, "dimpost": 'mm', "dimblk1": 'ClosedBlank', "dimblk2": 'ClosedBlank', "dimsah": 1})
dim.commit()
dim.dimension.update_dxf_attribs({"geometry": '*D7', "text_midpoint": (89.04996, 200.52503), "dimtype": 160})
dim = msp.add_linear_dim(base=(88.49721, 185.00003), p1=(82.60087, 180.50003), p2=(76.45996, 185.00003), angle=90, dimstyle='Standard$0', override={"dimdec": 1, "dimpost": 'mm'})
dim.commit()
dim.dimension.update_dxf_attribs({"geometry": '*D24', "text_midpoint": (88.49721, 182.75003)})

# ---------------------------------------------------------------- leaders
for points in [[(140.29117, 175.50003), (140.29117, 158.50003)], [(235.1946, 176.00003), (235.1946, 159.00003)], [(310.44996, 176.27503), (310.44996, 159.27503)], [(339.30998, 176.57003), (339.30998, 159.57003)], [(96.99996, 174.07895), (96.99996, 157.24774)]]:
    msp.add_leader(points, dimstyle='Standard', override={"dimscale": 1, "dimasz": 2, "dimgap": 0.09, "dimtad": 0, "dimldrblk": 'ClosedBlank'})
for points in [[(154.87496, 175.72503), (154.87496, 131.20279)], [(118.99996, 173.46503), (118.99996, 149.23901)]]:
    msp.add_leader(points, dimstyle='Standard', override={"dimscale": 1, "dimasz": 2, "dimgap": 0.09, "dimtad": 0, "dimldrblk": 'ClosedBlank'}, dxfattribs=at)

doc.saveas('drawing.dxf')
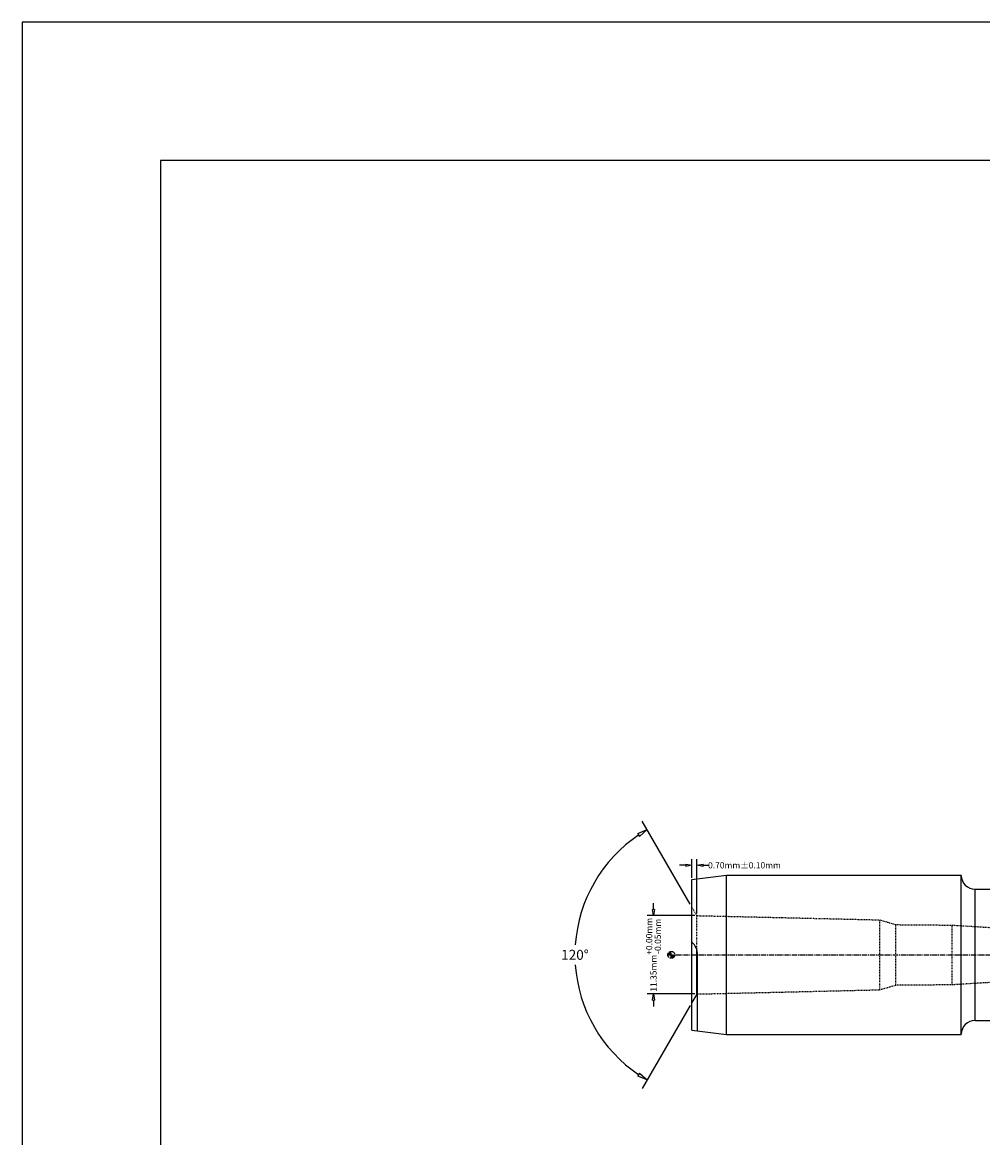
# Model space of a CAD drawing. Units: inches. Extents: x 0 to 594, y 0 to 420.
# Drawn here: x 0 to 139, y 259 to 420 of the extents above; entities that cross this region are included whole.
import ezdxf

# ---------------------------------------------------------------- set-up
doc = ezdxf.new("R2010")
doc.units = ezdxf.units.IN
doc.header["$MEASUREMENT"] = 0
doc.linetypes.add('CENTER2', pattern=[1.125, 0.75, -0.125, 0.125, -0.125])
doc.linetypes.add('HIDDEN2', pattern=[0.1875, 0.125, -0.0625])
for name, color, linetype in [('CENTER', 1, 'CENTER2'), ('CENTERLINE', 1, 'CENTER2'), ('HIDDEN', 5, 'HIDDEN2')]:
    doc.layers.add(name, color=color, linetype=linetype)
doc.dimstyles.get("Standard").update_dxf_attribs({"dimscale": 10, "dimtxt": 0.18, "dimasz": 0.18, "dimexe": 0.18, "dimexo": 0.0625, "dimgap": 0.09, "dimtad": 0, "dimtih": 1, "dimtoh": 1, "dimdec": 4, "dimzin": 0, "dimdsep": 46, "dimtxsty": 'Standard', "dimblk": 'CLOSEDBLANK', "dimcen": 0.09, "dimadec": 4, "dimazin": 0, "dimtfac": 1, "dimtdec": 4, "dimtofl": 0, "dimtmove": 0, "dimatfit": 3, "dimldrblk": 'CLOSEDBLANK', "dimfxl": 0, "dimtolj": 1, "dimtzin": 0, "dimarcsym": 0})
doc.dimstyles.new('Standard$0', dxfattribs={"dimscale": 10, "dimtxt": 0.18, "dimasz": 0.18, "dimexe": 0.18, "dimexo": 0.0625, "dimgap": 0.09, "dimtad": 0, "dimtih": 1, "dimtoh": 1, "dimdec": 4, "dimzin": 4, "dimdsep": 46, "dimtxsty": 'Standard', "dimblk": 'CLOSEDBLANK', "dimcen": 0.09, "dimadec": 5, "dimazin": 1, "dimtfac": 1, "dimtdec": 4, "dimtofl": 0, "dimtmove": 0, "dimatfit": 3, "dimldrblk": 'CLOSEDBLANK', "dimfxl": 0, "dimtolj": 1, "dimtzin": 0, "dimarcsym": 0})

# ---------------------------------------------------------------- blocks, each defined once
blk = doc.blocks.new('_ClosedBlank')
at = {"color": 0, "linetype": 'ByBlock', "lineweight": -2}
for p, q in [((-1, 0.17), (0, 0)), ((-1, 0.17), (-1, -0.17)), ((0, 0), (-1, -0.17))]:
    blk.add_line(p, q, dxfattribs=at)
blk = doc.blocks.new('*D29')
at = {"color": 0, "lineweight": -2}
for p, q in [((97, 296.16), (97, 298.86)), ((97.7, 290.99), (97.7, 298.86)), ((96.1, 297.96), (95.2, 297.96)), ((98.6, 297.96), (99.5, 297.96))]:
    blk.add_line(p, q, dxfattribs=at)
at = {"layer": 'Defpoints', "color": 0}
for p in [(97.7, 297.96), (97, 295.85), (97.7, 290.68)]:
    blk.add_point(p, dxfattribs=at)
at = {"color": 0, "lineweight": -2, "xscale": 0.8999999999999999, "yscale": 0.8999999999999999, "zscale": 0.8999999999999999}
blk.add_blockref('_ClosedBlank', (97, 297.96), dxfattribs=at)
at = {"color": 0, "lineweight": -2, "xscale": 0.8999999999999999, "yscale": 0.8999999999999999, "zscale": 0.8999999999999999, "rotation": 180}
blk.add_blockref('_ClosedBlank', (97.7, 297.96), dxfattribs=at)
at = {"color": 0, "insert": (104.6, 297.96), "char_height": 0.9, "attachment_point": 5}
blk.add_mtext('\\A1;0.70mm±0.10mm', dxfattribs=at)
blk = doc.blocks.new('*D30')
at = {"color": 0, "lineweight": -2}
for p, q in [((91.42, 291.58), (91.42, 292.48)), ((97.39, 290.68), (90.52, 290.68)), ((97.39, 279.33), (90.52, 279.33)), ((91.42, 278.43), (91.42, 277.53))]:
    blk.add_line(p, q, dxfattribs=at)
at = {"layer": 'Defpoints', "color": 0}
for p in [(91.42, 290.68), (97.7, 290.68), (97.7, 279.33)]:
    blk.add_point(p, dxfattribs=at)
at = {"color": 0, "lineweight": -2, "xscale": 0.8999999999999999, "yscale": 0.8999999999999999, "zscale": 0.8999999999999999}
for p, rotation in [((91.42, 290.68), 270), ((91.42, 279.33), 90)]:
    blk.add_blockref('_ClosedBlank', p, dxfattribs=dict(at, rotation=rotation))
at = {"color": 0, "insert": (91.42, 285), "char_height": 0.9, "attachment_point": 5, "rotation": 90}
blk.add_mtext('\\A1;11.35mm\\S+0.00mm^ -0.05mm;', dxfattribs=at)
blk = doc.blocks.new('*D31')
at = {"color": 0, "lineweight": -2}
for p, q in [((96.75, 292.32), (89.79, 304.37)), ((96.75, 277.68), (89.79, 265.63))]:
    blk.add_line(p, q, dxfattribs=at)
for start, end in [(123.9431, 176.0546), (183.9454, 236.0569)]:
    blk.add_arc((100.98, 285), 20.93, start, end, dxfattribs=at)
at = {"layer": 'Defpoints', "color": 0}
for p in [(81.31, 292.16), (97, 291.89), (97.7, 290.68), (97, 278.11), (97.7, 279.33)]:
    blk.add_point(p, dxfattribs=at)
at = {"color": 0, "lineweight": -2, "xscale": 1.44, "yscale": 1.44, "zscale": 1.44}
for p, rotation in [((90.51, 303.12), 31.97154143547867), ((90.51, 266.88), 328.0284585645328)]:
    blk.add_blockref('_ClosedBlank', p, dxfattribs=dict(at, rotation=rotation))
at = {"color": 0, "insert": (80.05, 285), "char_height": 1.44, "attachment_point": 5}
blk.add_mtext('\\A1;120°', dxfattribs=at)

msp = doc.modelspace()

# ---------------------------------------------------------------- hatches: boundary and pattern name
at = {"layer": 'CENTER'}
h = msp.add_hatch(dxfattribs=at)
h.set_pattern_fill('ANSI31', color=256, style=0)
h.set_pattern_definition([(45, (45, 235), (-0.08838835, 0.08838835), [])])
h.paths.add_polyline_path([(93.99996, 285.50003, 0.414213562), (93.49996, 285.00003), (93.99996, 285.00003)])
h.paths.add_polyline_path([(94.49996, 285.00003), (93.99996, 285.00003), (93.99996, 284.50003, 0.414213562)])

# ---------------------------------------------------------------- linework, layer by layer
for p, q in [((96.99996, 295.92111), (101.99996, 296.53503)), ((96.99996, 274.07895), (96.99996, 295.92111)), ((101.99996, 296.53503), (135.99996, 296.53503)), ((101.99996, 273.46503), (101.99996, 296.53503)), ((135.99996, 273.46503), (135.99996, 296.53503)), ((137.99996, 294.50003), (142.58238, 294.50003)), ((137.99996, 275.50003), (137.99996, 294.50003)), ((97.69996, 279.32501), (97.69996, 285.70003)), ((97.79996, 273.98072), (97.79996, 285.00003)), ((97.69996, 279.32501), (96.99996, 278.11258)), ((137.99996, 275.50003), (142.58238, 275.50003)), ((96.99996, 274.07895), (101.99996, 273.46503)), ((101.99996, 273.46503), (135.99996, 273.46503))]:
    msp.add_line(p, q)
for points in [[(0, 0), (594, 0), (594, 420), (0, 420)], [(20, 20), (574, 20), (574, 400), (20, 400)]]:
    msp.add_lwpolyline(points, close=True)
for centre, radius, start, end in [((137.99996, 296.50003), 2, 180, 270), ((95.29996, 285.00003), 2.5, 0, 47.156357), ((137.99996, 273.50003), 2, 90, 180)]:
    msp.add_arc(centre, radius, start, end)
msp.add_line((93.99996, 284.50003), (93.99996, 285.50003), dxfattribs=at)
msp.add_circle((93.99996, 285.00003), 0.5, dxfattribs=at)
at = {"layer": 'CENTERLINE'}
msp.add_line((93.49996, 285.00003), (514, 285.00003), dxfattribs=at)
at = {"layer": 'HIDDEN'}
for p, q in [((97.69996, 290.67505), (96.99996, 291.88748)), ((97.69996, 290.67505), (110.02996, 290.39203)), ((97.69996, 285.70003), (97.69996, 290.67505)), ((110.02996, 290.39203), (124.19996, 290.06003)), ((124.19996, 279.94003), (124.19996, 290.06003)), ((124.19996, 290.06003), (125.34996, 289.71503)), ((125.34996, 289.71503), (126.49996, 289.37003)), ((126.49996, 280.63003), (126.49996, 289.37003)), ((126.49996, 289.37003), (134.69996, 289.30003)), ((134.69996, 280.70003), (134.69996, 289.30003)), ((134.69996, 289.30003), (142.69996, 288.81003)), ((134.69996, 280.70003), (142.69996, 281.19003)), ((97.69996, 279.32501), (110.02996, 279.60803)), ((110.02996, 279.60803), (124.19996, 279.94003)), ((124.19996, 279.94003), (125.34996, 280.28503)), ((125.34996, 280.28503), (126.49996, 280.63003)), ((126.49996, 280.63003), (134.69996, 280.70003))]:
    msp.add_line(p, q, dxfattribs=at)

# ---------------------------------------------------------------- dimensions: what is measured, and where the dimension line sits
dim = msp.add_angular_dim_2l(base=(81.31022, 292.15795), line1=((97.69996, 290.67505), (96.99996, 291.88748)), line2=((97.69996, 279.32501), (96.99996, 278.11258)), dimstyle='Standard', override={"dimscale": 8, "dimadec": 0})
dim.commit()
dim.dimension.update_dxf_attribs({"geometry": '*D31', "text_midpoint": (80.04809, 285.00003)})
dim = msp.add_linear_dim(base=(97.69996, 297.95885), p1=(96.99996, 295.85003), p2=(97.69996, 290.67505), dimstyle='Standard$0', override={"dimscale": 5, "dimgap": 0.09, "dimdec": 2, "dimzin": 0, "dimpost": 'mm', "dimblk1": 'ClosedBlank', "dimblk2": 'ClosedBlank', "dimsah": 1, "dimtol": 1, "dimlim": 0, "dimtp": 0.1, "dimtm": 0.1, "dimtdec": 2})
dim.commit()
dim.dimension.update_dxf_attribs({"geometry": '*D29', "text_midpoint": (104.59996, 297.95885), "dimtype": 160})
dim = msp.add_linear_dim(base=(91.41508, 290.67505), p1=(97.69996, 279.32501), p2=(97.69996, 290.67505), angle=90, dimstyle='Standard$0', override={"dimscale": 5, "dimdec": 2, "dimpost": 'mm', "dimtol": 1, "dimtm": 0.05, "dimtdec": 2})
dim.commit()
dim.dimension.update_dxf_attribs({"geometry": '*D30', "text_midpoint": (91.41508, 285.00003), "dimtype": 160, "text_rotation": 90})

doc.saveas('drawing.dxf')
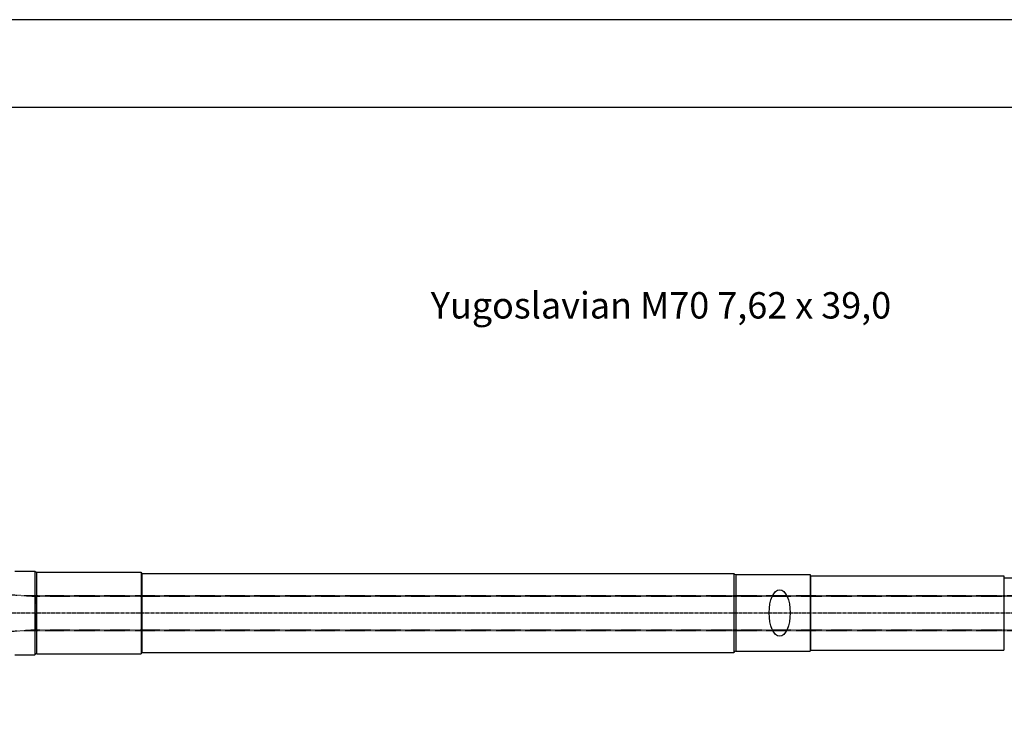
# Model space of a CAD drawing. Units: inches. Extents: x 0 to 594, y 0 to 420.
# Drawn here: x 139 to 363, y 259 to 420 of the extents above; entities that cross this region are included whole.
import ezdxf
from ezdxf.enums import TextEntityAlignment as Align

# ---------------------------------------------------------------- set-up
doc = ezdxf.new("R2010")
doc.units = ezdxf.units.IN
doc.header["$MEASUREMENT"] = 0
doc.linetypes.add('CENTER2', pattern=[1.125, 0.75, -0.125, 0.125, -0.125])
doc.linetypes.add('HIDDEN2', pattern=[0.1875, 0.125, -0.0625])
doc.layers.add('CENTERLINE', color=1, linetype='CENTER2')
doc.layers.add('HIDDEN', color=5, linetype='HIDDEN2')

msp = doc.modelspace()

# ---------------------------------------------------------------- linework, layer by layer
for p, q in [((137.99996, 294.50003), (142.58238, 294.50003)), ((142.58238, 294.50003), (142.58238, 275.50003)), ((142.99996, 294.27503), (166.74996, 294.27503)), ((142.99996, 275.72503), (142.99996, 294.27503)), ((166.74996, 294.27503), (166.74996, 275.72503)), ((166.99996, 294.00003), (301.55601, 294.00003)), ((166.99996, 276.00003), (166.99996, 294.00003)), ((301.55601, 294.00003), (301.55601, 276.00003)), ((301.99996, 293.72503), (318.89996, 293.72503)), ((301.99996, 293.72503), (301.99996, 276.27503)), ((318.89996, 293.72503), (318.89996, 276.27503)), ((318.99996, 293.45003), (362.99996, 293.45003)), ((318.99996, 293.45003), (318.99996, 276.55003)), ((362.99996, 293.45003), (362.99996, 276.55003)), ((363.09996, 293.02503), (403.89996, 293.02503)), ((142.99996, 275.72503), (166.74996, 275.72503)), ((166.99996, 276.00003), (301.55601, 276.00003)), ((301.99996, 276.27503), (318.89996, 276.27503)), ((318.99996, 276.55003), (362.99996, 276.55003)), ((137.99996, 275.50003), (142.58238, 275.50003))]:
    msp.add_line(p, q)
for points in [[(0, 0), (594, 0), (594, 420), (0, 420)], [(20, 20), (574, 20), (574, 400), (20, 400)]]:
    msp.add_lwpolyline(points, close=True)
for centre, radius, start, end in [((142.99996, 294.77503), 0.5, 213.367013, 270), ((166.99996, 294.25003), 0.25, 180, 270), ((302.00252, 294.22502), 0.5, 206.7428404, 270), ((318.99996, 293.55003), 0.1, 180, 270), ((363.09996, 293.12503), 0.1, 180, 270), ((142.99996, 275.22503), 0.5, 90, 146.632987), ((166.99996, 275.75003), 0.25, 90, 180), ((301.99996, 275.77503), 0.5, 90, 153.256316), ((318.99996, 276.45003), 0.1, 90, 180), ((363.09996, 276.87503), 0.1, 90, 180)]:
    msp.add_arc(centre, radius, start, end)
msp.add_ellipse((311.99996, 285.00003), major_axis=(0, -5.27871), ratio=0.453419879)
at = {"layer": 'CENTERLINE'}
msp.add_line((93.49996, 285.00003), (514, 285.00003), dxfattribs=at)
at = {"layer": 'HIDDEN'}
for p, q in [((134.69996, 289.30003), (142.69996, 288.81003)), ((140.2118, 288.96243), (510.99996, 288.96243)), ((142.69996, 288.81003), (510.99996, 288.81003)), ((142.69996, 281.19003), (142.69996, 288.81003)), ((134.69996, 280.70003), (142.69996, 281.19003)), ((140.2118, 281.03763), (510.99996, 281.03763)), ((142.69996, 281.19003), (510.99996, 281.19003))]:
    msp.add_line(p, q, dxfattribs=at)

# ---------------------------------------------------------------- texts
msp.add_text('Yugoslavian M70 7,62 x 39,0', height=6).set_placement((285, 355), align=Align.MIDDLE_CENTER)

doc.saveas('drawing.dxf')
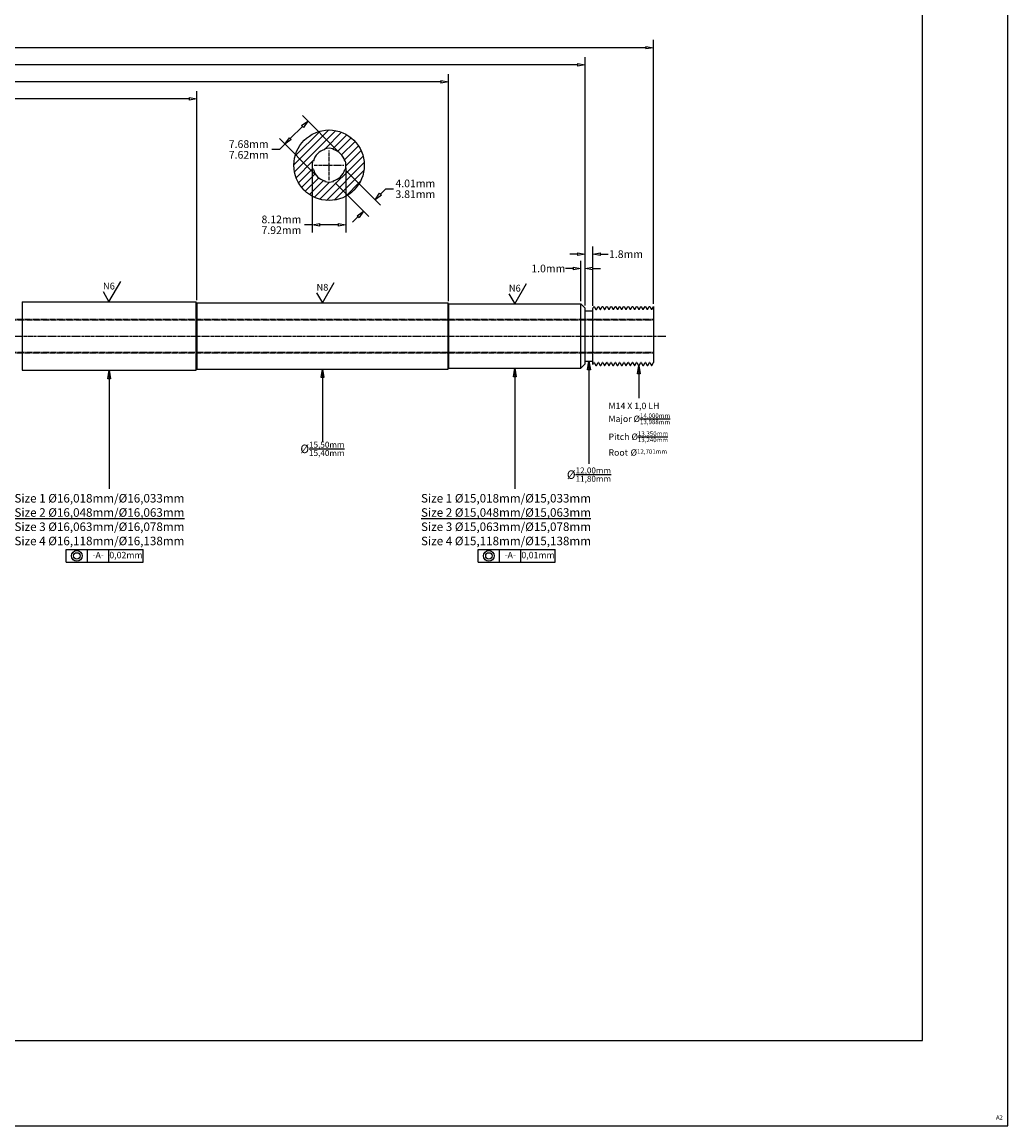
# Model space of a CAD drawing. Units: inches. Extents: x 0 to 594, y 0 to 420.
# Drawn here: x 363 to 594, y 0 to 259 of the extents above; entities that cross this region are included whole.
import ezdxf
from ezdxf.enums import TextEntityAlignment as Align

# ---------------------------------------------------------------- set-up
doc = ezdxf.new("R2010")
doc.units = ezdxf.units.IN
doc.header["$MEASUREMENT"] = 0
doc.linetypes.add('CENTER2', pattern=[1.125, 0.75, -0.125, 0.125, -0.125])
doc.linetypes.add('HIDDEN2', pattern=[0.1875, 0.125, -0.0625])
for name, color, linetype in [('CENTER', 1, 'CENTER2'), ('CENTERLINE', 1, 'CENTER2'), ('HATCH', 253, 'Continuous'), ('HIDDEN', 5, 'HIDDEN2'), ('TEXT', 5, 'Continuous')]:
    doc.layers.add(name, color=color, linetype=linetype)
doc.dimstyles.get("Standard").update_dxf_attribs({"dimscale": 10, "dimtxt": 0.18, "dimasz": 0.18, "dimexe": 0.18, "dimexo": 0.0625, "dimgap": 0.09, "dimtad": 0, "dimtih": 1, "dimtoh": 1, "dimdec": 4, "dimzin": 0, "dimdsep": 46, "dimtxsty": 'Standard', "dimblk": 'CLOSEDBLANK', "dimcen": 0.09, "dimadec": 4, "dimazin": 0, "dimtfac": 1, "dimtdec": 4, "dimtofl": 0, "dimtmove": 0, "dimatfit": 3, "dimldrblk": 'CLOSEDBLANK', "dimfxl": 0, "dimtolj": 1, "dimtzin": 0, "dimarcsym": 0})
doc.dimstyles.new('Standard$0', dxfattribs={"dimscale": 10, "dimtxt": 0.18, "dimasz": 0.18, "dimexe": 0.18, "dimexo": 0.0625, "dimgap": 0.09, "dimtad": 0, "dimtih": 1, "dimtoh": 1, "dimdec": 4, "dimzin": 4, "dimdsep": 46, "dimtxsty": 'Standard', "dimblk": 'CLOSEDBLANK', "dimcen": 0.09, "dimadec": 5, "dimazin": 1, "dimtfac": 1, "dimtdec": 4, "dimtofl": 0, "dimtmove": 0, "dimatfit": 3, "dimldrblk": 'CLOSEDBLANK', "dimfxl": 0, "dimtolj": 1, "dimtzin": 0, "dimarcsym": 0})

# ---------------------------------------------------------------- blocks, each defined once
blk = doc.blocks.new('_ClosedBlank')
at = {"color": 0, "linetype": 'ByBlock', "lineweight": -2}
for p, q in [((-1, 0.17), (0, 0)), ((-1, 0.17), (-1, -0.17)), ((0, 0), (-1, -0.17))]:
    blk.add_line(p, q, dxfattribs=at)
blk = doc.blocks.new('*D21')
at = {"color": 0, "lineweight": -2}
for p, q in [((97, 196.55), (97, 254.33)), ((511, 192.52), (511, 254.33)), ((98.8, 252.53), (298.15, 252.53)), ((509.2, 252.53), (309.85, 252.53))]:
    blk.add_line(p, q, dxfattribs=at)
at = {"layer": 'Defpoints', "color": 0}
for p in [(511, 252.53), (97, 195.92), (511, 191.89)]:
    blk.add_point(p, dxfattribs=at)
at = {"color": 0, "lineweight": -2, "xscale": 1.8, "yscale": 1.8, "zscale": 1.8, "rotation": 180}
blk.add_blockref('_ClosedBlank', (97, 252.53), dxfattribs=at)
at = {"color": 0, "lineweight": -2, "xscale": 1.8, "yscale": 1.8, "zscale": 1.8}
blk.add_blockref('_ClosedBlank', (511, 252.53), dxfattribs=at)
at = {"color": 0, "insert": (304, 252.53), "char_height": 1.8, "attachment_point": 5}
blk.add_mtext('\\A1;414.0mm', dxfattribs=at)
blk = doc.blocks.new('*D16')
at = {"color": 0, "lineweight": -2}
for p, q in [((97, 196.55), (97, 242.33)), ((98.8, 240.53), (244.5, 240.53)), ((402.2, 240.53), (256.5, 240.53)), ((404, 193.38), (404, 242.33))]:
    blk.add_line(p, q, dxfattribs=at)
at = {"layer": 'Defpoints', "color": 0}
for p in [(97, 240.53), (97, 195.92), (404, 192.75)]:
    blk.add_point(p, dxfattribs=at)
at = {"color": 0, "lineweight": -2, "xscale": 1.8, "yscale": 1.8, "zscale": 1.8, "rotation": 180}
blk.add_blockref('_ClosedBlank', (97, 240.53), dxfattribs=at)
at = {"color": 0, "lineweight": -2, "xscale": 1.8, "yscale": 1.8, "zscale": 1.8}
blk.add_blockref('_ClosedBlank', (404, 240.53), dxfattribs=at)
at = {"color": 0, "insert": (250.5, 240.53), "char_height": 1.8, "attachment_point": 5}
blk.add_mtext('\\A1;307.0mm', dxfattribs=at)
blk = doc.blocks.new('*D17')
at = {"color": 0, "lineweight": -2}
for p, q in [((97, 196.55), (97, 246.33)), ((463, 193.15), (463, 246.33)), ((98.8, 244.53), (273.85, 244.53)), ((461.2, 244.53), (286.15, 244.53))]:
    blk.add_line(p, q, dxfattribs=at)
at = {"layer": 'Defpoints', "color": 0}
for p in [(97, 244.53), (97, 195.92), (463, 192.53)]:
    blk.add_point(p, dxfattribs=at)
at = {"color": 0, "lineweight": -2, "xscale": 1.8, "yscale": 1.8, "zscale": 1.8, "rotation": 180}
blk.add_blockref('_ClosedBlank', (97, 244.53), dxfattribs=at)
at = {"color": 0, "lineweight": -2, "xscale": 1.8, "yscale": 1.8, "zscale": 1.8}
blk.add_blockref('_ClosedBlank', (463, 244.53), dxfattribs=at)
at = {"color": 0, "insert": (280, 244.53), "char_height": 1.8, "attachment_point": 5}
blk.add_mtext('\\A1;366.0mm', dxfattribs=at)
blk = doc.blocks.new('*D18')
at = {"color": 0, "lineweight": -2}
for p, q in [((97, 196.55), (97, 250.33)), ((98.8, 248.53), (289.85, 248.53)), ((493.2, 248.53), (302.15, 248.53)), ((495, 192.15), (495, 250.33))]:
    blk.add_line(p, q, dxfattribs=at)
at = {"layer": 'Defpoints', "color": 0}
for p in [(495, 248.53), (97, 195.92), (495, 191.53)]:
    blk.add_point(p, dxfattribs=at)
at = {"color": 0, "lineweight": -2, "xscale": 1.8, "yscale": 1.8, "zscale": 1.8, "rotation": 180}
blk.add_blockref('_ClosedBlank', (97, 248.53), dxfattribs=at)
at = {"color": 0, "lineweight": -2, "xscale": 1.8, "yscale": 1.8, "zscale": 1.8}
blk.add_blockref('_ClosedBlank', (495, 248.53), dxfattribs=at)
at = {"color": 0, "insert": (296, 248.53), "char_height": 1.8, "attachment_point": 5}
blk.add_mtext('\\A1;398.0mm', dxfattribs=at)
blk = doc.blocks.new('*D19')
at = {"color": 0, "lineweight": -2}
for p, q in [((495, 192.15), (495, 205.97)), ((496.75, 192.08), (496.75, 205.97)), ((493.2, 204.17), (491.4, 204.17)), ((498.55, 204.17), (500.35, 204.17))]:
    blk.add_line(p, q, dxfattribs=at)
at = {"layer": 'Defpoints', "color": 0}
for p in [(496.75, 204.17), (495, 191.53), (496.75, 191.46)]:
    blk.add_point(p, dxfattribs=at)
at = {"color": 0, "lineweight": -2, "xscale": 1.8, "yscale": 1.8, "zscale": 1.8}
blk.add_blockref('_ClosedBlank', (495, 204.17), dxfattribs=at)
at = {"color": 0, "lineweight": -2, "xscale": 1.8, "yscale": 1.8, "zscale": 1.8, "rotation": 180}
blk.add_blockref('_ClosedBlank', (496.75, 204.17), dxfattribs=at)
at = {"color": 0, "insert": (504.55, 204.17), "char_height": 1.8, "attachment_point": 5}
blk.add_mtext('\\A1;1.8mm', dxfattribs=at)
blk = doc.blocks.new('*D20')
at = {"color": 0, "lineweight": -2}
for p, q in [((494, 193.15), (494, 202.62)), ((495, 192.15), (495, 202.62)), ((492.2, 200.82), (490.4, 200.82)), ((496.8, 200.82), (498.6, 200.82))]:
    blk.add_line(p, q, dxfattribs=at)
at = {"layer": 'Defpoints', "color": 0}
for p in [(494, 200.82), (494, 192.53), (495, 191.53)]:
    blk.add_point(p, dxfattribs=at)
at = {"color": 0, "lineweight": -2, "xscale": 1.8, "yscale": 1.8, "zscale": 1.8}
blk.add_blockref('_ClosedBlank', (494, 200.82), dxfattribs=at)
at = {"color": 0, "lineweight": -2, "xscale": 1.8, "yscale": 1.8, "zscale": 1.8, "rotation": 180}
blk.add_blockref('_ClosedBlank', (495, 200.82), dxfattribs=at)
at = {"color": 0, "insert": (486.35, 200.82), "char_height": 1.8, "attachment_point": 5}
blk.add_mtext('\\A1;1.0mm', dxfattribs=at)
blk = doc.blocks.new('*D26')
at = {"color": 0, "lineweight": -2}
for p, q in [((439.12, 223.57), (447.03, 215.66)), ((436.43, 220.88), (444.34, 212.97)), ((447.03, 218.2), (448.31, 219.48)), ((448.31, 219.48), (450.11, 219.48)), ((441.8, 212.97), (440.52, 211.69))]:
    blk.add_line(p, q, dxfattribs=at)
at = {"layer": 'Defpoints', "color": 0}
for p in [(438.68, 224.01), (435.99, 221.32), (445.76, 216.93)]:
    blk.add_point(p, dxfattribs=at)
at = {"color": 0, "lineweight": -2, "xscale": 1.8, "yscale": 1.8, "zscale": 1.8}
for p, rotation in [((445.76, 216.93), 225), ((443.07, 214.24), 45)]:
    blk.add_blockref('_ClosedBlank', p, dxfattribs=dict(at, rotation=rotation))
at = {"color": 0, "insert": (455.21, 219.48), "char_height": 1.8, "attachment_point": 5}
blk.add_mtext('\\A1;\\S4.01mm^ 3.81mm;', dxfattribs=at)
blk = doc.blocks.new('*D27')
at = {"color": 0, "lineweight": -2}
for p, q in [((437.25, 228.14), (428.77, 236.62)), ((428.77, 234.08), (425.92, 231.23)), ((431.86, 222.75), (423.38, 231.23)), ((423.38, 228.69), (421.58, 228.69)), ((424.65, 229.96), (423.38, 228.69))]:
    blk.add_line(p, q, dxfattribs=at)
at = {"layer": 'Defpoints', "color": 0}
for p in [(424.65, 229.96), (437.69, 227.69), (432.31, 222.31)]:
    blk.add_point(p, dxfattribs=at)
at = {"color": 0, "lineweight": -2, "xscale": 1.8, "yscale": 1.8, "zscale": 1.8}
for p, rotation in [((430.04, 235.35), 45), ((424.65, 229.96), 225)]:
    blk.add_blockref('_ClosedBlank', p, dxfattribs=dict(at, rotation=rotation))
at = {"color": 0, "insert": (416.18, 228.69), "char_height": 1.8, "attachment_point": 5}
blk.add_mtext('\\A1;\\S7.68mm^ 7.62mm;', dxfattribs=at)
blk = doc.blocks.new('*D28')
at = {"color": 0, "lineweight": -2}
for p, q in [((431.04, 224.38), (431.04, 209.25)), ((438.96, 224.38), (438.96, 209.25)), ((431.04, 211.05), (429.24, 211.05)), ((437.16, 211.05), (432.84, 211.05))]:
    blk.add_line(p, q, dxfattribs=at)
at = {"layer": 'Defpoints', "color": 0}
for p in [(431.04, 225), (438.96, 225), (438.96, 211.05)]:
    blk.add_point(p, dxfattribs=at)
at = {"color": 0, "lineweight": -2, "xscale": 1.8, "yscale": 1.8, "zscale": 1.8, "rotation": 180}
blk.add_blockref('_ClosedBlank', (431.04, 211.05), dxfattribs=at)
at = {"color": 0, "lineweight": -2, "xscale": 1.8, "yscale": 1.8, "zscale": 1.8}
blk.add_blockref('_ClosedBlank', (438.96, 211.05), dxfattribs=at)
at = {"color": 0, "insert": (423.84, 211.05), "char_height": 1.8, "attachment_point": 5}
blk.add_mtext('\\A1;\\S8.12mm^ 7.92mm;', dxfattribs=at)

msp = doc.modelspace()

# ---------------------------------------------------------------- hatches: boundary and pattern name
at = {"layer": 'HATCH'}
h = msp.add_hatch(dxfattribs=at)
h.set_pattern_fill('ANSI31', color=256, scale=10, style=0)
h.set_pattern_definition([(45, (138.5568, 50), (-0.8838835, 0.8838835), [])])
h.paths.add_polyline_path([(426.75, 225.00003, 1), (443.25, 225.00003, 1)])
h.paths.add_polyline_path([(438.68018, 225.98613), (438.82507, 226.02495, -0.131652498), (438.82507, 223.97511), (438.68018, 224.01393, -0.267949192), (435.9861, 221.31985), (436.02492, 221.17496, -0.131652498), (433.97508, 221.17496), (434.0139, 221.31985, -0.267949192), (431.31982, 224.01393), (431.17493, 223.97511, -0.131652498), (431.17493, 226.02495), (431.31982, 225.98613, -0.267949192), (434.0139, 228.68021), (433.97508, 228.8251, -0.131652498), (436.02492, 228.8251), (435.9861, 228.68021, -0.267949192)], flags=16)

# ---------------------------------------------------------------- linework, layer by layer
for p, q in [((434.0139, 228.68021), (433.97508, 228.8251)), ((435.9861, 228.68021), (436.02492, 228.8251)), ((431.31982, 225.98613), (431.17493, 226.02495)), ((438.68018, 225.98613), (438.82507, 226.02495)), ((431.31982, 224.01393), (431.17493, 223.97511)), ((438.68018, 224.01393), (438.82507, 223.97511)), ((434.0139, 221.31985), (433.97508, 221.17496)), ((435.9861, 221.31985), (436.02492, 221.17496)), ((383.44996, 193.02503), (386.19959, 197.78753)), ((433.44996, 192.75003), (436.19959, 197.51253)), ((478.49996, 192.52503), (481.24959, 197.28753)), ((382.07514, 195.40628), (383.44996, 193.02503)), ((432.07514, 195.13128), (433.44996, 192.75003)), ((477.12514, 194.90628), (478.49996, 192.52503)), ((363.09996, 193.02503), (403.89996, 193.02503)), ((363.09996, 193.02503), (363.09996, 176.97503)), ((403.89996, 176.97503), (403.89996, 193.02503)), ((403.99996, 192.75003), (462.89996, 192.75003)), ((403.99996, 192.75003), (403.99996, 177.25003)), ((462.89996, 177.25003), (462.89996, 192.75003)), ((462.99996, 192.52503), (493.99996, 192.52503)), ((462.99996, 192.52503), (462.99996, 177.47503)), ((493.99996, 177.47503), (493.99996, 192.52503)), ((493.99996, 192.52503), (494.99996, 191.52503)), ((494.99996, 178.47503), (494.99996, 191.52503)), ((496.74996, 191.45876), (496.99996, 191.89178)), ((496.74996, 178.32479), (496.74996, 191.45876)), ((496.99996, 191.89178), (497.12496, 191.89178)), ((497.12496, 191.89178), (497.52079, 191.20617)), ((497.60413, 191.20617), (497.99996, 191.89178)), ((497.99996, 191.89178), (498.12496, 191.89178)), ((498.12496, 191.89178), (498.52079, 191.20617)), ((498.60413, 191.20617), (498.99996, 191.89178)), ((498.99996, 191.89178), (499.12496, 191.89178)), ((499.12496, 191.89178), (499.52079, 191.20617)), ((499.60413, 191.20617), (499.99996, 191.89178)), ((499.99996, 191.89178), (500.12496, 191.89178)), ((500.12496, 191.89178), (500.52079, 191.20617)), ((500.60413, 191.20617), (500.99996, 191.89178)), ((500.99996, 191.89178), (501.12496, 191.89178)), ((501.12496, 191.89178), (501.52079, 191.20617)), ((501.60413, 191.20617), (501.99996, 191.89178)), ((501.99996, 191.89178), (502.12496, 191.89178)), ((502.12496, 191.89178), (502.52079, 191.20617)), ((502.60413, 191.20617), (502.99996, 191.89178)), ((502.99996, 191.89178), (503.12496, 191.89178)), ((503.12496, 191.89178), (503.52079, 191.20617)), ((503.60413, 191.20617), (503.99996, 191.89178)), ((503.99996, 191.89178), (504.12496, 191.89178)), ((504.12496, 191.89178), (504.52079, 191.20617)), ((504.60413, 191.20617), (504.99996, 191.89178)), ((504.99996, 191.89178), (505.12496, 191.89178)), ((505.12496, 191.89178), (505.52079, 191.20617)), ((505.60413, 191.20617), (505.99996, 191.89178)), ((505.99996, 191.89178), (506.12496, 191.89178)), ((506.12496, 191.89178), (506.52079, 191.20617)), ((506.60413, 191.20617), (506.99996, 191.89178)), ((506.99996, 191.89178), (507.12496, 191.89178)), ((507.12496, 191.89178), (507.52079, 191.20617)), ((507.60413, 191.20617), (507.99996, 191.89178)), ((507.99996, 191.89178), (508.12496, 191.89178)), ((508.12496, 191.89178), (508.52079, 191.20617)), ((508.60413, 191.20617), (508.99996, 191.89178)), ((508.99996, 191.89178), (509.12496, 191.89178)), ((509.12496, 191.89178), (509.52079, 191.20617)), ((509.60413, 191.20617), (509.99996, 191.89178)), ((509.99996, 191.89178), (510.12496, 191.89178)), ((510.12496, 191.89178), (510.52079, 191.20617)), ((510.60413, 191.20617), (510.99996, 191.89178)), ((510.99996, 191.89178), (510.99996, 178.7578)), ((494.99996, 190.90003), (496.74996, 190.90003)), ((497.49996, 191.24226), (497.52079, 191.20617)), ((497.52079, 191.20617), (497.60413, 191.20617)), ((497.60413, 191.20617), (497.52079, 191.20617)), ((498.49996, 191.24226), (498.52079, 191.20617)), ((498.52079, 191.20617), (498.60413, 191.20617)), ((498.60413, 191.20617), (498.52079, 191.20617)), ((499.52079, 191.20617), (499.60413, 191.20617)), ((499.60413, 191.20617), (499.52079, 191.20617)), ((500.60413, 191.20617), (500.52079, 191.20617)), ((501.60413, 191.20617), (501.52079, 191.20617)), ((502.60413, 191.20617), (502.52079, 191.20617)), ((503.60413, 191.20617), (503.52079, 191.20617)), ((504.60413, 191.20617), (504.52079, 191.20617)), ((505.60413, 191.20617), (505.52079, 191.20617)), ((506.60413, 191.20617), (506.52079, 191.20617)), ((507.60413, 191.20617), (507.52079, 191.20617)), ((508.60413, 191.20617), (508.52079, 191.20617)), ((509.60413, 191.20617), (509.52079, 191.20617)), ((510.60413, 191.20617), (510.52079, 191.20617)), ((493.99996, 177.47503), (494.99996, 178.47503)), ((494.99996, 179.10003), (496.74996, 179.10003)), ((496.74996, 178.32479), (497.02079, 178.79389)), ((497.02079, 178.79389), (497.10413, 178.79389)), ((497.10413, 178.79389), (497.02079, 178.79389)), ((497.10413, 178.79389), (497.49996, 178.10828)), ((497.62496, 178.10828), (498.02079, 178.79389)), ((498.02079, 178.79389), (498.10413, 178.79389)), ((498.10413, 178.79389), (498.02079, 178.79389)), ((498.10413, 178.79389), (498.49996, 178.10828)), ((498.62496, 178.10828), (499.02079, 178.79389)), ((499.02079, 178.79389), (499.10413, 178.79389)), ((499.10413, 178.79389), (499.02079, 178.79389)), ((499.10413, 178.79389), (499.49996, 178.10828)), ((499.62496, 178.10828), (500.02079, 178.79389)), ((500.10413, 178.79389), (500.02079, 178.79389)), ((500.10413, 178.79389), (500.49996, 178.10828)), ((500.62496, 178.10828), (501.02079, 178.79389)), ((501.10413, 178.79389), (501.02079, 178.79389)), ((501.10413, 178.79389), (501.49996, 178.10828)), ((501.62496, 178.10828), (502.02079, 178.79389)), ((502.10413, 178.79389), (502.02079, 178.79389)), ((502.10413, 178.79389), (502.49996, 178.10828)), ((502.62496, 178.10828), (503.02079, 178.79389)), ((503.10413, 178.79389), (503.02079, 178.79389)), ((503.10413, 178.79389), (503.49996, 178.10828)), ((503.62496, 178.10828), (504.02079, 178.79389)), ((504.10413, 178.79389), (504.02079, 178.79389)), ((504.10413, 178.79389), (504.49996, 178.10828)), ((504.62496, 178.10828), (505.02079, 178.79389)), ((505.10413, 178.79389), (505.02079, 178.79389)), ((505.10413, 178.79389), (505.49996, 178.10828)), ((505.62496, 178.10828), (506.02079, 178.79389)), ((506.10413, 178.79389), (506.02079, 178.79389)), ((506.10413, 178.79389), (506.49996, 178.10828)), ((506.62496, 178.10828), (507.02079, 178.79389)), ((507.10413, 178.79389), (507.02079, 178.79389)), ((507.10413, 178.79389), (507.49996, 178.10828)), ((507.62496, 178.10828), (508.02079, 178.79389)), ((508.10413, 178.79389), (508.02079, 178.79389)), ((508.10413, 178.79389), (508.49996, 178.10828)), ((508.62496, 178.10828), (509.02079, 178.79389)), ((509.10413, 178.79389), (509.02079, 178.79389)), ((509.10413, 178.79389), (509.49996, 178.10828)), ((509.62496, 178.10828), (510.02079, 178.79389)), ((510.10413, 178.79389), (510.02079, 178.79389)), ((510.10413, 178.79389), (510.49996, 178.10828)), ((510.62496, 178.10828), (510.99996, 178.7578)), ((363.09996, 176.97503), (403.89996, 176.97503)), ((403.99996, 177.25003), (462.89996, 177.25003)), ((462.99996, 177.47503), (493.99996, 177.47503)), ((497.49996, 178.10828), (497.62496, 178.10828)), ((498.49996, 178.10828), (498.62496, 178.10828)), ((499.49996, 178.10828), (499.62496, 178.10828)), ((500.49996, 178.10828), (500.62496, 178.10828)), ((501.49996, 178.10828), (501.62496, 178.10828)), ((502.49996, 178.10828), (502.62496, 178.10828)), ((503.49996, 178.10828), (503.62496, 178.10828)), ((504.49996, 178.10828), (504.62496, 178.10828)), ((505.49996, 178.10828), (505.62496, 178.10828)), ((506.49996, 178.10828), (506.62496, 178.10828)), ((507.49996, 178.10828), (507.62496, 178.10828)), ((508.49996, 178.10828), (508.62496, 178.10828)), ((509.49996, 178.10828), (509.62496, 178.10828)), ((510.49996, 178.10828), (510.62496, 178.10828))]:
    msp.add_line(p, q)
for points in [[(0, 0), (594, 0), (594, 420), (0, 420)], [(20, 20), (574, 20), (574, 400), (20, 400)]]:
    msp.add_lwpolyline(points, close=True)
msp.add_circle((435, 225.00003), 8.25)
for centre, radius, start, end in [((435, 225.00003), 3.81, 105, 165), ((435, 225.00003), 3.96, 75, 105), ((435, 225.00003), 3.81, 15, 75), ((435, 225.00003), 3.96, 165, 195), ((435, 225.00003), 3.96, 345, 15), ((435, 225.00003), 3.81, 195, 255), ((435, 225.00003), 3.81, 285, 345), ((435, 225.00003), 3.96, 255, 285), ((403.99996, 192.85003), 0.1, 180, 270), ((462.99996, 192.62503), 0.1, 180, 270), ((403.99996, 177.15003), 0.1, 90, 180), ((462.99996, 177.37503), 0.1, 90, 180)]:
    msp.add_arc(centre, radius, start, end)
at = {"layer": 'CENTER'}
for p, q in [((435, 221.53503), (435, 228.46503)), ((431.535, 225.00003), (438.465, 225.00003))]:
    msp.add_line(p, q, dxfattribs=at)
at = {"layer": 'CENTERLINE'}
msp.add_line((93.49996, 185.00003), (513.99996, 185.00003), dxfattribs=at)
at = {"layer": 'HIDDEN'}
for p, q in [((140.2118, 188.96243), (510.99996, 188.96243)), ((142.69996, 188.81003), (510.99996, 188.81003)), ((140.2118, 181.03763), (510.99996, 181.03763)), ((142.69996, 181.19003), (510.99996, 181.19003))]:
    msp.add_line(p, q, dxfattribs=at)
at = {"layer": 'TEXT', "color": 7}
for p, q in [((373.42424, 132), (373.42424, 135)), ((373.42424, 135), (378.42424, 135)), ((378.42424, 135), (383.42424, 135)), ((378.42424, 132), (378.42424, 135)), ((383.42424, 135), (391.42424, 135)), ((383.42424, 132), (383.42424, 135)), ((391.42424, 132), (391.42424, 135)), ((469.93457, 132), (469.93457, 135)), ((469.93457, 135), (474.93457, 135)), ((474.93457, 135), (479.93457, 135)), ((474.93457, 132), (474.93457, 135)), ((479.93457, 135), (487.93457, 135)), ((479.93457, 132), (479.93457, 135)), ((487.93457, 132), (487.93457, 135)), ((373.42424, 132), (378.42424, 132)), ((378.42424, 132), (383.42424, 132)), ((383.42424, 132), (391.42424, 132)), ((469.93457, 132), (474.93457, 132)), ((474.93457, 132), (479.93457, 132)), ((479.93457, 132), (487.93457, 132))]:
    msp.add_line(p, q, dxfattribs=at)
for centre, radius in [((375.92424, 133.5), 1.25), ((472.43457, 133.5), 1.25), ((375.92424, 133.5), 0.75), ((472.43457, 133.5), 0.75)]:
    msp.add_circle(centre, radius, dxfattribs=at)

# ---------------------------------------------------------------- texts
for s, p in [('N6', (383.44996, 195.40628)), ('N8', (433.44996, 195.13128)), ('N6', (478.49996, 194.90628))]:
    msp.add_text(s, height=1.5875).set_placement(p, align=Align.BOTTOM_CENTER)
msp.add_text('A2', height=1).set_placement((592, 2), align=Align.MIDDLE_CENTER)
at = {"char_height": 2, "width": 10.5482646, "attachment_point": 2}
for s, insert in [('\\A1;%%C{\\H0.7x;\\S15,50mm/15,40mm;}', (433.44996, 160.25003)), ('\\A1;%%C{\\H0.7x;\\S12,00mm/11,80mm;}', (495.87496, 154.21478))]:
    msp.add_mtext(s, dxfattribs=dict(at, insert=insert))
at = {"layer": 'TEXT', "color": 7}
for s, insert, char_height, width, attachment_point in [('\\A1;{\\H0.75x;M14 X 1,0 LH\\PMajor %%C\\H0.7x;\\S14,000mm/13,988mm;\\H1.429x;\\PPitch %%C\\H0.7x;\\S13,350mm/13,240mm;\\H1.429x;\\PRoot} {\\H0.75x;%%C\\H0.7x;12,701mm}', (500.45201, 169.37094), 2, 19.3860592, 1), ('\\A1;Size 1 %%C16,018mm/%%C16,033mm\\P{\\LSize 2 %%C16,048mm/%%C16,063mm}\\PSize 3 %%C16,063mm/%%C16,078mm\\PSize 4 %%C16,118mm/%%C16,138mm', (361.31639, 148), 2, 48.5376086, 1), ('\\A1;Size 1 %%C15,018mm/%%C15,033mm\\P{\\LSize 2 %%C15,048mm/%%C15,063mm}\\PSize 3 %%C15,063mm/%%C15,078mm\\PSize 4 %%C15,118mm/%%C15,138mm', (456.54314, 148), 2, 48.5376086, 1), ('-A-', (380.92424, 133.5), 1.5, 1.19634, 5), ('0,02mm', (387.42424, 133.5), 1.5, 6.6720954, 5), ('-A-', (477.43457, 133.5), 1.5, 1.19634, 5), ('0,01mm', (483.93457, 133.5), 1.5, 6.6720954, 5)]:
    msp.add_mtext(s, dxfattribs=dict(at, insert=insert, char_height=char_height, width=width, attachment_point=attachment_point))

# ---------------------------------------------------------------- dimensions: what is measured, and where the dimension line sits
for base, p1, p2, picture, middle in [((510.99996, 252.52503), (96.99996, 195.92111), (510.99996, 191.89178), '*D21', (303.99996, 252.52503)), ((494.99996, 248.52503), (96.99996, 195.92111), (494.99996, 191.52503), '*D18', (295.99996, 248.52503)), ((96.99996, 244.52503), (462.99996, 192.52503), (96.99996, 195.92111), '*D17', (279.99996, 244.52503)), ((96.99996, 240.52503), (403.99996, 192.75003), (96.99996, 195.92111), '*D16', (250.49996, 240.52503)), ((496.749960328, 204.1660716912), (494.999960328, 191.5250289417), (496.749960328, 191.4587630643), '*D19', (504.549960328, 204.1660716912))]:
    dim = msp.add_linear_dim(base=base, p1=p1, p2=p2, dimstyle='Standard$0', override={"dimscale": 10, "dimdec": 1, "dimpost": 'mm', "dimblk1": 'ClosedBlank', "dimblk2": 'ClosedBlank', "dimsah": 1})
    dim.commit()
    dim.dimension.update_dxf_attribs({"geometry": picture, "text_midpoint": middle})
for base, p1, p2, angle, override, picture, middle in [((424.64969, 229.96218), (437.69408, 227.69411), (432.30592, 222.30595), 225, {"dimgap": 0.09, "dimpost": 'mm', "dimtol": 0, "dimlim": 1, "dimtp": 0.06, "dimtm": 1e-09, "dimtdec": 2}, '*D27', (416.1769, 228.68939)), ((445.76198, 216.93213), (435.9861, 221.31985), (438.68018, 224.01393), 45, {"dimgap": 0.09, "dimpost": 'mm', "dimtol": 0, "dimlim": 1, "dimtp": 0.2, "dimtm": 1e-09, "dimtdec": 2}, '*D26', (455.20756, 219.47771)), ((493.99996, 200.81887), (494.99996, 191.52503), (493.99996, 192.52503), 180, {"dimscale": 10, "dimdec": 1, "dimpost": 'mm', "dimblk1": 'ClosedBlank', "dimblk2": 'ClosedBlank', "dimsah": 1}, '*D20', (486.34996, 200.81887))]:
    dim = msp.add_linear_dim(base=base, p1=p1, p2=p2, angle=angle, dimstyle='Standard$0', override=override)
    dim.commit()
    dim.dimension.update_dxf_attribs({"geometry": picture, "text_midpoint": middle})
dim = msp.add_linear_dim(base=(438.96, 211.05221), p1=(431.04, 225.00003), p2=(438.96, 225.00003), dimstyle='Standard$0', override={"dimgap": 0.09, "dimpost": 'mm', "dimtol": 0, "dimlim": 1, "dimtp": 0.2, "dimtm": 1e-09, "dimtdec": 2})
dim.commit()
dim.dimension.update_dxf_attribs({"geometry": '*D28', "text_midpoint": (423.84, 211.05221), "dimtype": 160})

# ---------------------------------------------------------------- leaders
for points in [[(495.87496, 179.10003), (495.87496, 155.08332)], [(433.44996, 177.25003), (433.44996, 160.25003)], [(507.56246, 178.10828), (507.56246, 170.45928)]]:
    msp.add_leader(points, dimstyle='Standard', override={"dimscale": 1, "dimasz": 2, "dimgap": 0.09, "dimtad": 0, "dimldrblk": 'ClosedBlank'})
for points in [[(383.49996, 176.97503), (383.49996, 149.23901)], [(478.49996, 177.47503), (478.49996, 149.23901)]]:
    msp.add_leader(points, dimstyle='Standard', override={"dimscale": 1, "dimasz": 2, "dimgap": 0.09, "dimtad": 0, "dimldrblk": 'ClosedBlank'}, dxfattribs=at)

doc.saveas('drawing.dxf')
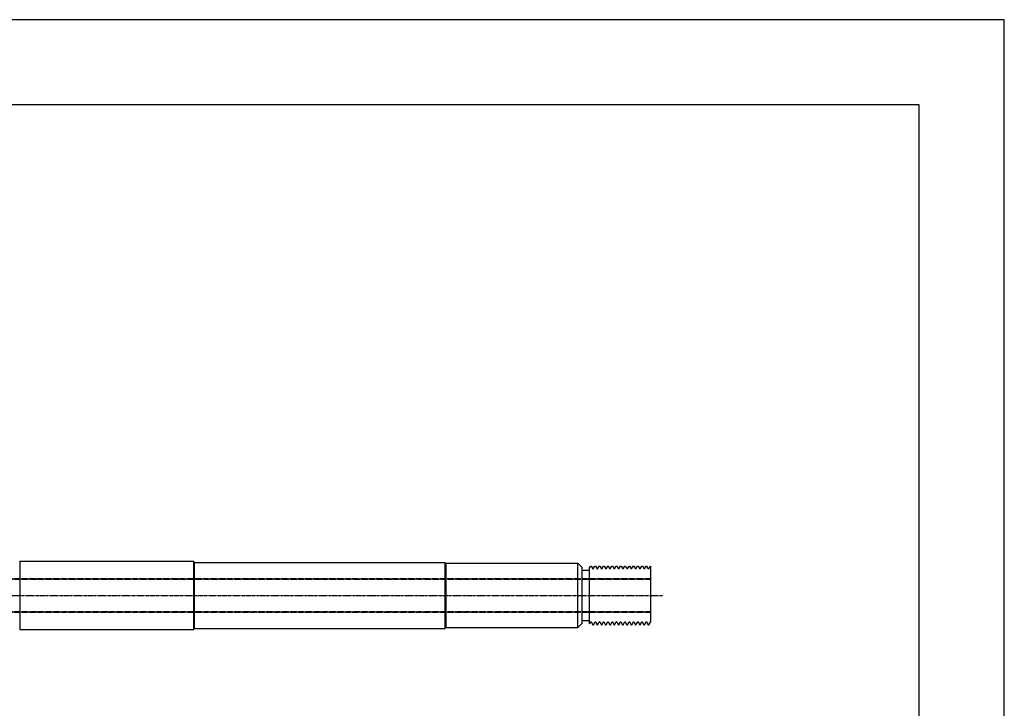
# Model space of a CAD drawing. Units: inches. Extents: x 0 to 594, y 0 to 420.
# Drawn here: x 363 to 594, y 259 to 420 of the extents above; entities that cross this region are included whole.
import ezdxf

# ---------------------------------------------------------------- set-up
doc = ezdxf.new("R2010")
doc.units = ezdxf.units.IN
doc.header["$MEASUREMENT"] = 0
doc.linetypes.add('CENTER2', pattern=[1.125, 0.75, -0.125, 0.125, -0.125])
doc.linetypes.add('HIDDEN2', pattern=[0.1875, 0.125, -0.0625])
doc.layers.add('CENTERLINE', color=1, linetype='CENTER2')
doc.layers.add('HIDDEN', color=5, linetype='HIDDEN2')

msp = doc.modelspace()

# ---------------------------------------------------------------- linework, layer by layer
for p, q in [((363.09996, 293.02503), (403.89996, 293.02503)), ((363.09996, 293.02503), (363.09996, 276.97503)), ((403.89996, 276.97503), (403.89996, 293.02503)), ((403.99996, 292.75003), (462.89996, 292.75003)), ((403.99996, 292.75003), (403.99996, 277.25003)), ((462.89996, 277.25003), (462.89996, 292.75003)), ((462.99996, 292.52503), (493.99996, 292.52503)), ((462.99996, 292.52503), (462.99996, 277.47503)), ((493.99996, 277.47503), (493.99996, 292.52503)), ((493.99996, 292.52503), (494.99996, 291.52503)), ((494.99996, 278.47503), (494.99996, 291.52503)), ((496.74996, 291.45876), (496.99996, 291.89178)), ((496.74996, 278.32479), (496.74996, 291.45876)), ((496.99996, 291.89178), (497.12496, 291.89178)), ((497.12496, 291.89178), (497.52079, 291.20617)), ((497.49996, 291.24226), (497.52079, 291.20617)), ((497.52079, 291.20617), (497.60413, 291.20617)), ((497.60413, 291.20617), (497.52079, 291.20617)), ((497.60413, 291.20617), (497.99996, 291.89178)), ((497.99996, 291.89178), (498.12496, 291.89178)), ((498.12496, 291.89178), (498.52079, 291.20617)), ((498.49996, 291.24226), (498.52079, 291.20617)), ((498.52079, 291.20617), (498.60413, 291.20617)), ((498.60413, 291.20617), (498.52079, 291.20617)), ((498.60413, 291.20617), (498.99996, 291.89178)), ((498.99996, 291.89178), (499.12496, 291.89178)), ((499.12496, 291.89178), (499.52079, 291.20617)), ((499.52079, 291.20617), (499.60413, 291.20617)), ((499.60413, 291.20617), (499.52079, 291.20617)), ((499.60413, 291.20617), (499.99996, 291.89178)), ((499.99996, 291.89178), (500.12496, 291.89178)), ((500.12496, 291.89178), (500.52079, 291.20617)), ((500.60413, 291.20617), (500.52079, 291.20617)), ((500.60413, 291.20617), (500.99996, 291.89178)), ((500.99996, 291.89178), (501.12496, 291.89178)), ((501.12496, 291.89178), (501.52079, 291.20617)), ((501.60413, 291.20617), (501.52079, 291.20617)), ((501.60413, 291.20617), (501.99996, 291.89178)), ((501.99996, 291.89178), (502.12496, 291.89178)), ((502.12496, 291.89178), (502.52079, 291.20617)), ((502.60413, 291.20617), (502.52079, 291.20617)), ((502.60413, 291.20617), (502.99996, 291.89178)), ((502.99996, 291.89178), (503.12496, 291.89178)), ((503.12496, 291.89178), (503.52079, 291.20617)), ((503.60413, 291.20617), (503.52079, 291.20617)), ((503.60413, 291.20617), (503.99996, 291.89178)), ((503.99996, 291.89178), (504.12496, 291.89178)), ((504.12496, 291.89178), (504.52079, 291.20617)), ((504.60413, 291.20617), (504.52079, 291.20617)), ((504.60413, 291.20617), (504.99996, 291.89178)), ((504.99996, 291.89178), (505.12496, 291.89178)), ((505.12496, 291.89178), (505.52079, 291.20617)), ((505.60413, 291.20617), (505.52079, 291.20617)), ((505.60413, 291.20617), (505.99996, 291.89178)), ((505.99996, 291.89178), (506.12496, 291.89178)), ((506.12496, 291.89178), (506.52079, 291.20617)), ((506.60413, 291.20617), (506.52079, 291.20617)), ((506.60413, 291.20617), (506.99996, 291.89178)), ((506.99996, 291.89178), (507.12496, 291.89178)), ((507.12496, 291.89178), (507.52079, 291.20617)), ((507.60413, 291.20617), (507.52079, 291.20617)), ((507.60413, 291.20617), (507.99996, 291.89178)), ((507.99996, 291.89178), (508.12496, 291.89178)), ((508.12496, 291.89178), (508.52079, 291.20617)), ((508.60413, 291.20617), (508.52079, 291.20617)), ((508.60413, 291.20617), (508.99996, 291.89178)), ((508.99996, 291.89178), (509.12496, 291.89178)), ((509.12496, 291.89178), (509.52079, 291.20617)), ((509.60413, 291.20617), (509.52079, 291.20617)), ((509.60413, 291.20617), (509.99996, 291.89178)), ((509.99996, 291.89178), (510.12496, 291.89178)), ((510.12496, 291.89178), (510.52079, 291.20617)), ((510.60413, 291.20617), (510.52079, 291.20617)), ((510.60413, 291.20617), (510.99996, 291.89178)), ((510.99996, 291.89178), (510.99996, 278.7578)), ((494.99996, 290.90003), (496.74996, 290.90003)), ((403.99996, 277.25003), (462.89996, 277.25003)), ((462.99996, 277.47503), (493.99996, 277.47503)), ((493.99996, 277.47503), (494.99996, 278.47503)), ((494.99996, 279.10003), (496.74996, 279.10003)), ((496.74996, 278.32479), (497.02079, 278.79389)), ((497.02079, 278.79389), (497.10413, 278.79389)), ((497.10413, 278.79389), (497.02079, 278.79389)), ((497.10413, 278.79389), (497.49996, 278.10828)), ((497.49996, 278.10828), (497.62496, 278.10828)), ((497.62496, 278.10828), (498.02079, 278.79389)), ((498.02079, 278.79389), (498.10413, 278.79389)), ((498.10413, 278.79389), (498.02079, 278.79389)), ((498.10413, 278.79389), (498.49996, 278.10828)), ((498.49996, 278.10828), (498.62496, 278.10828)), ((498.62496, 278.10828), (499.02079, 278.79389)), ((499.02079, 278.79389), (499.10413, 278.79389)), ((499.10413, 278.79389), (499.02079, 278.79389)), ((499.10413, 278.79389), (499.49996, 278.10828)), ((499.49996, 278.10828), (499.62496, 278.10828)), ((499.62496, 278.10828), (500.02079, 278.79389)), ((500.10413, 278.79389), (500.02079, 278.79389)), ((500.10413, 278.79389), (500.49996, 278.10828)), ((500.49996, 278.10828), (500.62496, 278.10828)), ((500.62496, 278.10828), (501.02079, 278.79389)), ((501.10413, 278.79389), (501.02079, 278.79389)), ((501.10413, 278.79389), (501.49996, 278.10828)), ((501.49996, 278.10828), (501.62496, 278.10828)), ((501.62496, 278.10828), (502.02079, 278.79389)), ((502.10413, 278.79389), (502.02079, 278.79389)), ((502.10413, 278.79389), (502.49996, 278.10828)), ((502.49996, 278.10828), (502.62496, 278.10828)), ((502.62496, 278.10828), (503.02079, 278.79389)), ((503.10413, 278.79389), (503.02079, 278.79389)), ((503.10413, 278.79389), (503.49996, 278.10828)), ((503.49996, 278.10828), (503.62496, 278.10828)), ((503.62496, 278.10828), (504.02079, 278.79389)), ((504.10413, 278.79389), (504.02079, 278.79389)), ((504.10413, 278.79389), (504.49996, 278.10828)), ((504.49996, 278.10828), (504.62496, 278.10828)), ((504.62496, 278.10828), (505.02079, 278.79389)), ((505.10413, 278.79389), (505.02079, 278.79389)), ((505.10413, 278.79389), (505.49996, 278.10828)), ((505.49996, 278.10828), (505.62496, 278.10828)), ((505.62496, 278.10828), (506.02079, 278.79389)), ((506.10413, 278.79389), (506.02079, 278.79389)), ((506.10413, 278.79389), (506.49996, 278.10828)), ((506.49996, 278.10828), (506.62496, 278.10828)), ((506.62496, 278.10828), (507.02079, 278.79389)), ((507.10413, 278.79389), (507.02079, 278.79389)), ((507.10413, 278.79389), (507.49996, 278.10828)), ((507.49996, 278.10828), (507.62496, 278.10828)), ((507.62496, 278.10828), (508.02079, 278.79389)), ((508.10413, 278.79389), (508.02079, 278.79389)), ((508.10413, 278.79389), (508.49996, 278.10828)), ((508.49996, 278.10828), (508.62496, 278.10828)), ((508.62496, 278.10828), (509.02079, 278.79389)), ((509.10413, 278.79389), (509.02079, 278.79389)), ((509.10413, 278.79389), (509.49996, 278.10828)), ((509.49996, 278.10828), (509.62496, 278.10828)), ((509.62496, 278.10828), (510.02079, 278.79389)), ((510.10413, 278.79389), (510.02079, 278.79389)), ((510.10413, 278.79389), (510.49996, 278.10828)), ((510.49996, 278.10828), (510.62496, 278.10828)), ((510.62496, 278.10828), (510.99996, 278.7578)), ((363.09996, 276.97503), (403.89996, 276.97503))]:
    msp.add_line(p, q)
for points in [[(0, 0), (594, 0), (594, 420), (0, 420)], [(20, 20), (574, 20), (574, 400), (20, 400)]]:
    msp.add_lwpolyline(points, close=True)
for centre, start, end in [((403.99996, 292.85003), 180, 270), ((462.99996, 292.62503), 180, 270), ((403.99996, 277.15003), 90, 180), ((462.99996, 277.37503), 90, 180)]:
    msp.add_arc(centre, 0.1, start, end)
at = {"layer": 'CENTERLINE'}
msp.add_line((93.49996, 285.00003), (514, 285.00003), dxfattribs=at)
at = {"layer": 'HIDDEN'}
for p, q in [((140.2118, 288.96243), (510.99996, 288.96243)), ((142.69996, 288.81003), (510.99996, 288.81003)), ((140.2118, 281.03763), (510.99996, 281.03763)), ((142.69996, 281.19003), (510.99996, 281.19003))]:
    msp.add_line(p, q, dxfattribs=at)

doc.saveas('drawing.dxf')
